# Generated by FakeRAM 2.0 (routing-friendly)
VERSION 5.7 ;
BUSBITCHARS "[]" ;
PROPERTYDEFINITIONS
  MACRO width INTEGER ;
  MACRO depth INTEGER ;
  MACRO banks INTEGER ;
END PROPERTYDEFINITIONS
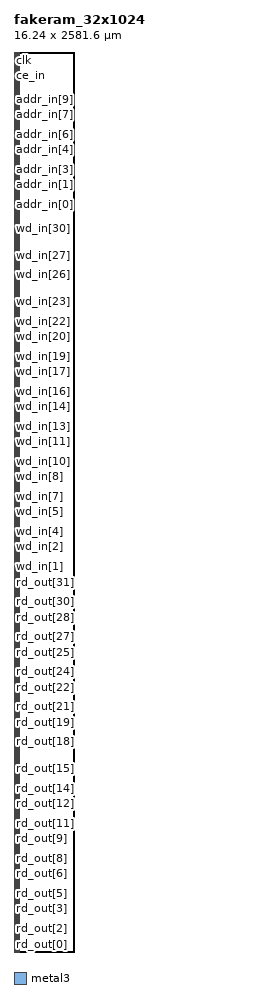
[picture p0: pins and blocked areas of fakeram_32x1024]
MACRO fakeram_32x1024
  PROPERTY width 32 ;
  PROPERTY depth 1024 ;
  PROPERTY banks 1 ;
  FOREIGN fakeram_32x1024 0 0 ;
  SYMMETRY X Y R90 ;
  SIZE 16.240 BY 2581.600 ;
  CLASS BLOCK ;
  PIN rd_out[0]
    DIRECTION OUTPUT ;
    USE SIGNAL ;
    PORT
      LAYER metal3 ;
      RECT 1.000 0.140 3.000 0.210 ;
    END
    PORT
      LAYER metal3 ;
      RECT 1.000 0.105 4.000 0.245 ;
    END
  END rd_out[0]
  PIN rd_out[1]
    DIRECTION OUTPUT ;
    USE SIGNAL ;
    PORT
      LAYER metal3 ;
      RECT 1.000 33.600 3.000 33.670 ;
    END
    PORT
      LAYER metal3 ;
      RECT 1.000 33.565 4.000 33.705 ;
    END
  END rd_out[1]
  PIN rd_out[2]
    DIRECTION OUTPUT ;
    USE SIGNAL ;
    PORT
      LAYER metal3 ;
      RECT 1.000 67.060 3.000 67.130 ;
    END
    PORT
      LAYER metal3 ;
      RECT 1.000 67.025 4.000 67.165 ;
    END
  END rd_out[2]
  PIN rd_out[3]
    DIRECTION OUTPUT ;
    USE SIGNAL ;
    PORT
      LAYER metal3 ;
      RECT 1.000 100.520 3.000 100.590 ;
    END
    PORT
      LAYER metal3 ;
      RECT 1.000 100.485 4.000 100.625 ;
    END
  END rd_out[3]
  PIN rd_out[4]
    DIRECTION OUTPUT ;
    USE SIGNAL ;
    PORT
      LAYER metal3 ;
      RECT 1.000 133.980 3.000 134.050 ;
    END
    PORT
      LAYER metal3 ;
      RECT 1.000 133.945 4.000 134.085 ;
    END
  END rd_out[4]
  PIN rd_out[5]
    DIRECTION OUTPUT ;
    USE SIGNAL ;
    PORT
      LAYER metal3 ;
      RECT 1.000 167.440 3.000 167.510 ;
    END
    PORT
      LAYER metal3 ;
      RECT 1.000 167.405 4.000 167.545 ;
    END
  END rd_out[5]
  PIN rd_out[6]
    DIRECTION OUTPUT ;
    USE SIGNAL ;
    PORT
      LAYER metal3 ;
      RECT 1.000 200.900 3.000 200.970 ;
    END
    PORT
      LAYER metal3 ;
      RECT 1.000 200.865 4.000 201.005 ;
    END
  END rd_out[6]
  PIN rd_out[7]
    DIRECTION OUTPUT ;
    USE SIGNAL ;
    PORT
      LAYER metal3 ;
      RECT 1.000 234.360 3.000 234.430 ;
    END
    PORT
      LAYER metal3 ;
      RECT 1.000 234.325 4.000 234.465 ;
    END
  END rd_out[7]
  PIN rd_out[8]
    DIRECTION OUTPUT ;
    USE SIGNAL ;
    PORT
      LAYER metal3 ;
      RECT 1.000 267.820 3.000 267.890 ;
    END
    PORT
      LAYER metal3 ;
      RECT 1.000 267.785 4.000 267.925 ;
    END
  END rd_out[8]
  PIN rd_out[9]
    DIRECTION OUTPUT ;
    USE SIGNAL ;
    PORT
      LAYER metal3 ;
      RECT 1.000 301.280 3.000 301.350 ;
    END
    PORT
      LAYER metal3 ;
      RECT 1.000 301.245 4.000 301.385 ;
    END
  END rd_out[9]
  PIN rd_out[10]
    DIRECTION OUTPUT ;
    USE SIGNAL ;
    PORT
      LAYER metal3 ;
      RECT 1.000 334.740 3.000 334.810 ;
    END
    PORT
      LAYER metal3 ;
      RECT 1.000 334.705 4.000 334.845 ;
    END
  END rd_out[10]
  PIN rd_out[11]
    DIRECTION OUTPUT ;
    USE SIGNAL ;
    PORT
      LAYER metal3 ;
      RECT 1.000 368.200 3.000 368.270 ;
    END
    PORT
      LAYER metal3 ;
      RECT 1.000 368.165 4.000 368.305 ;
    END
  END rd_out[11]
  PIN rd_out[12]
    DIRECTION OUTPUT ;
    USE SIGNAL ;
    PORT
      LAYER metal3 ;
      RECT 1.000 401.660 3.000 401.730 ;
    END
    PORT
      LAYER metal3 ;
      RECT 1.000 401.625 4.000 401.765 ;
    END
  END rd_out[12]
  PIN rd_out[13]
    DIRECTION OUTPUT ;
    USE SIGNAL ;
    PORT
      LAYER metal3 ;
      RECT 1.000 435.120 3.000 435.190 ;
    END
    PORT
      LAYER metal3 ;
      RECT 1.000 435.085 4.000 435.225 ;
    END
  END rd_out[13]
  PIN rd_out[14]
    DIRECTION OUTPUT ;
    USE SIGNAL ;
    PORT
      LAYER metal3 ;
      RECT 1.000 468.580 3.000 468.650 ;
    END
    PORT
      LAYER metal3 ;
      RECT 1.000 468.545 4.000 468.685 ;
    END
  END rd_out[14]
  PIN rd_out[15]
    DIRECTION OUTPUT ;
    USE SIGNAL ;
    PORT
      LAYER metal3 ;
      RECT 1.000 502.040 3.000 502.110 ;
    END
    PORT
      LAYER metal3 ;
      RECT 1.000 502.005 4.000 502.145 ;
    END
  END rd_out[15]
  PIN rd_out[16]
    DIRECTION OUTPUT ;
    USE SIGNAL ;
    PORT
      LAYER metal3 ;
      RECT 1.000 535.500 3.000 535.570 ;
    END
    PORT
      LAYER metal3 ;
      RECT 1.000 535.465 4.000 535.605 ;
    END
  END rd_out[16]
  PIN rd_out[17]
    DIRECTION OUTPUT ;
    USE SIGNAL ;
    PORT
      LAYER metal3 ;
      RECT 1.000 568.960 3.000 569.030 ;
    END
    PORT
      LAYER metal3 ;
      RECT 1.000 568.925 4.000 569.065 ;
    END
  END rd_out[17]
  PIN rd_out[18]
    DIRECTION OUTPUT ;
    USE SIGNAL ;
    PORT
      LAYER metal3 ;
      RECT 1.000 602.420 3.000 602.490 ;
    END
    PORT
      LAYER metal3 ;
      RECT 1.000 602.385 4.000 602.525 ;
    END
  END rd_out[18]
  PIN rd_out[19]
    DIRECTION OUTPUT ;
    USE SIGNAL ;
    PORT
      LAYER metal3 ;
      RECT 1.000 635.880 3.000 635.950 ;
    END
    PORT
      LAYER metal3 ;
      RECT 1.000 635.845 4.000 635.985 ;
    END
  END rd_out[19]
  PIN rd_out[20]
    DIRECTION OUTPUT ;
    USE SIGNAL ;
    PORT
      LAYER metal3 ;
      RECT 1.000 669.340 3.000 669.410 ;
    END
    PORT
      LAYER metal3 ;
      RECT 1.000 669.305 4.000 669.445 ;
    END
  END rd_out[20]
  PIN rd_out[21]
    DIRECTION OUTPUT ;
    USE SIGNAL ;
    PORT
      LAYER metal3 ;
      RECT 1.000 702.800 3.000 702.870 ;
    END
    PORT
      LAYER metal3 ;
      RECT 1.000 702.765 4.000 702.905 ;
    END
  END rd_out[21]
  PIN rd_out[22]
    DIRECTION OUTPUT ;
    USE SIGNAL ;
    PORT
      LAYER metal3 ;
      RECT 1.000 736.260 3.000 736.330 ;
    END
    PORT
      LAYER metal3 ;
      RECT 1.000 736.225 4.000 736.365 ;
    END
  END rd_out[22]
  PIN rd_out[23]
    DIRECTION OUTPUT ;
    USE SIGNAL ;
    PORT
      LAYER metal3 ;
      RECT 1.000 769.720 3.000 769.790 ;
    END
    PORT
      LAYER metal3 ;
      RECT 1.000 769.685 4.000 769.825 ;
    END
  END rd_out[23]
  PIN rd_out[24]
    DIRECTION OUTPUT ;
    USE SIGNAL ;
    PORT
      LAYER metal3 ;
      RECT 1.000 803.180 3.000 803.250 ;
    END
    PORT
      LAYER metal3 ;
      RECT 1.000 803.145 4.000 803.285 ;
    END
  END rd_out[24]
  PIN rd_out[25]
    DIRECTION OUTPUT ;
    USE SIGNAL ;
    PORT
      LAYER metal3 ;
      RECT 1.000 836.640 3.000 836.710 ;
    END
    PORT
      LAYER metal3 ;
      RECT 1.000 836.605 4.000 836.745 ;
    END
  END rd_out[25]
  PIN rd_out[26]
    DIRECTION OUTPUT ;
    USE SIGNAL ;
    PORT
      LAYER metal3 ;
      RECT 1.000 870.100 3.000 870.170 ;
    END
    PORT
      LAYER metal3 ;
      RECT 1.000 870.065 4.000 870.205 ;
    END
  END rd_out[26]
  PIN rd_out[27]
    DIRECTION OUTPUT ;
    USE SIGNAL ;
    PORT
      LAYER metal3 ;
      RECT 1.000 903.560 3.000 903.630 ;
    END
    PORT
      LAYER metal3 ;
      RECT 1.000 903.525 4.000 903.665 ;
    END
  END rd_out[27]
  PIN rd_out[28]
    DIRECTION OUTPUT ;
    USE SIGNAL ;
    PORT
      LAYER metal3 ;
      RECT 1.000 937.020 3.000 937.090 ;
    END
    PORT
      LAYER metal3 ;
      RECT 1.000 936.985 4.000 937.125 ;
    END
  END rd_out[28]
  PIN rd_out[29]
    DIRECTION OUTPUT ;
    USE SIGNAL ;
    PORT
      LAYER metal3 ;
      RECT 1.000 970.480 3.000 970.550 ;
    END
    PORT
      LAYER metal3 ;
      RECT 1.000 970.445 4.000 970.585 ;
    END
  END rd_out[29]
  PIN rd_out[30]
    DIRECTION OUTPUT ;
    USE SIGNAL ;
    PORT
      LAYER metal3 ;
      RECT 1.000 1003.940 3.000 1004.010 ;
    END
    PORT
      LAYER metal3 ;
      RECT 1.000 1003.905 4.000 1004.045 ;
    END
  END rd_out[30]
  PIN rd_out[31]
    DIRECTION OUTPUT ;
    USE SIGNAL ;
    PORT
      LAYER metal3 ;
      RECT 1.000 1037.400 3.000 1037.470 ;
    END
    PORT
      LAYER metal3 ;
      RECT 1.000 1037.365 4.000 1037.505 ;
    END
  END rd_out[31]
  PIN wd_in[0]
    DIRECTION INPUT ;
    USE SIGNAL ;
    PORT
      LAYER metal3 ;
      RECT 1.000 1072.400 3.000 1072.470 ;
    END
    PORT
      LAYER metal3 ;
      RECT 1.000 1072.365 4.000 1072.505 ;
    END
  END wd_in[0]
  PIN wd_in[1]
    DIRECTION INPUT ;
    USE SIGNAL ;
    PORT
      LAYER metal3 ;
      RECT 1.000 1105.860 3.000 1105.930 ;
    END
    PORT
      LAYER metal3 ;
      RECT 1.000 1105.825 4.000 1105.965 ;
    END
  END wd_in[1]
  PIN wd_in[2]
    DIRECTION INPUT ;
    USE SIGNAL ;
    PORT
      LAYER metal3 ;
      RECT 1.000 1139.320 3.000 1139.390 ;
    END
    PORT
      LAYER metal3 ;
      RECT 1.000 1139.285 4.000 1139.425 ;
    END
  END wd_in[2]
  PIN wd_in[3]
    DIRECTION INPUT ;
    USE SIGNAL ;
    PORT
      LAYER metal3 ;
      RECT 1.000 1172.780 3.000 1172.850 ;
    END
    PORT
      LAYER metal3 ;
      RECT 1.000 1172.745 4.000 1172.885 ;
    END
  END wd_in[3]
  PIN wd_in[4]
    DIRECTION INPUT ;
    USE SIGNAL ;
    PORT
      LAYER metal3 ;
      RECT 1.000 1206.240 3.000 1206.310 ;
    END
    PORT
      LAYER metal3 ;
      RECT 1.000 1206.205 4.000 1206.345 ;
    END
  END wd_in[4]
  PIN wd_in[5]
    DIRECTION INPUT ;
    USE SIGNAL ;
    PORT
      LAYER metal3 ;
      RECT 1.000 1239.700 3.000 1239.770 ;
    END
    PORT
      LAYER metal3 ;
      RECT 1.000 1239.665 4.000 1239.805 ;
    END
  END wd_in[5]
  PIN wd_in[6]
    DIRECTION INPUT ;
    USE SIGNAL ;
    PORT
      LAYER metal3 ;
      RECT 1.000 1273.160 3.000 1273.230 ;
    END
    PORT
      LAYER metal3 ;
      RECT 1.000 1273.125 4.000 1273.265 ;
    END
  END wd_in[6]
  PIN wd_in[7]
    DIRECTION INPUT ;
    USE SIGNAL ;
    PORT
      LAYER metal3 ;
      RECT 1.000 1306.620 3.000 1306.690 ;
    END
    PORT
      LAYER metal3 ;
      RECT 1.000 1306.585 4.000 1306.725 ;
    END
  END wd_in[7]
  PIN wd_in[8]
    DIRECTION INPUT ;
    USE SIGNAL ;
    PORT
      LAYER metal3 ;
      RECT 1.000 1340.080 3.000 1340.150 ;
    END
    PORT
      LAYER metal3 ;
      RECT 1.000 1340.045 4.000 1340.185 ;
    END
  END wd_in[8]
  PIN wd_in[9]
    DIRECTION INPUT ;
    USE SIGNAL ;
    PORT
      LAYER metal3 ;
      RECT 1.000 1373.540 3.000 1373.610 ;
    END
    PORT
      LAYER metal3 ;
      RECT 1.000 1373.505 4.000 1373.645 ;
    END
  END wd_in[9]
  PIN wd_in[10]
    DIRECTION INPUT ;
    USE SIGNAL ;
    PORT
      LAYER metal3 ;
      RECT 1.000 1407.000 3.000 1407.070 ;
    END
    PORT
      LAYER metal3 ;
      RECT 1.000 1406.965 4.000 1407.105 ;
    END
  END wd_in[10]
  PIN wd_in[11]
    DIRECTION INPUT ;
    USE SIGNAL ;
    PORT
      LAYER metal3 ;
      RECT 1.000 1440.460 3.000 1440.530 ;
    END
    PORT
      LAYER metal3 ;
      RECT 1.000 1440.425 4.000 1440.565 ;
    END
  END wd_in[11]
  PIN wd_in[12]
    DIRECTION INPUT ;
    USE SIGNAL ;
    PORT
      LAYER metal3 ;
      RECT 1.000 1473.920 3.000 1473.990 ;
    END
    PORT
      LAYER metal3 ;
      RECT 1.000 1473.885 4.000 1474.025 ;
    END
  END wd_in[12]
  PIN wd_in[13]
    DIRECTION INPUT ;
    USE SIGNAL ;
    PORT
      LAYER metal3 ;
      RECT 1.000 1507.380 3.000 1507.450 ;
    END
    PORT
      LAYER metal3 ;
      RECT 1.000 1507.345 4.000 1507.485 ;
    END
  END wd_in[13]
  PIN wd_in[14]
    DIRECTION INPUT ;
    USE SIGNAL ;
    PORT
      LAYER metal3 ;
      RECT 1.000 1540.840 3.000 1540.910 ;
    END
    PORT
      LAYER metal3 ;
      RECT 1.000 1540.805 4.000 1540.945 ;
    END
  END wd_in[14]
  PIN wd_in[15]
    DIRECTION INPUT ;
    USE SIGNAL ;
    PORT
      LAYER metal3 ;
      RECT 1.000 1574.300 3.000 1574.370 ;
    END
    PORT
      LAYER metal3 ;
      RECT 1.000 1574.265 4.000 1574.405 ;
    END
  END wd_in[15]
  PIN wd_in[16]
    DIRECTION INPUT ;
    USE SIGNAL ;
    PORT
      LAYER metal3 ;
      RECT 1.000 1607.760 3.000 1607.830 ;
    END
    PORT
      LAYER metal3 ;
      RECT 1.000 1607.725 4.000 1607.865 ;
    END
  END wd_in[16]
  PIN wd_in[17]
    DIRECTION INPUT ;
    USE SIGNAL ;
    PORT
      LAYER metal3 ;
      RECT 1.000 1641.220 3.000 1641.290 ;
    END
    PORT
      LAYER metal3 ;
      RECT 1.000 1641.185 4.000 1641.325 ;
    END
  END wd_in[17]
  PIN wd_in[18]
    DIRECTION INPUT ;
    USE SIGNAL ;
    PORT
      LAYER metal3 ;
      RECT 1.000 1674.680 3.000 1674.750 ;
    END
    PORT
      LAYER metal3 ;
      RECT 1.000 1674.645 4.000 1674.785 ;
    END
  END wd_in[18]
  PIN wd_in[19]
    DIRECTION INPUT ;
    USE SIGNAL ;
    PORT
      LAYER metal3 ;
      RECT 1.000 1708.140 3.000 1708.210 ;
    END
    PORT
      LAYER metal3 ;
      RECT 1.000 1708.105 4.000 1708.245 ;
    END
  END wd_in[19]
  PIN wd_in[20]
    DIRECTION INPUT ;
    USE SIGNAL ;
    PORT
      LAYER metal3 ;
      RECT 1.000 1741.600 3.000 1741.670 ;
    END
    PORT
      LAYER metal3 ;
      RECT 1.000 1741.565 4.000 1741.705 ;
    END
  END wd_in[20]
  PIN wd_in[21]
    DIRECTION INPUT ;
    USE SIGNAL ;
    PORT
      LAYER metal3 ;
      RECT 1.000 1775.060 3.000 1775.130 ;
    END
    PORT
      LAYER metal3 ;
      RECT 1.000 1775.025 4.000 1775.165 ;
    END
  END wd_in[21]
  PIN wd_in[22]
    DIRECTION INPUT ;
    USE SIGNAL ;
    PORT
      LAYER metal3 ;
      RECT 1.000 1808.520 3.000 1808.590 ;
    END
    PORT
      LAYER metal3 ;
      RECT 1.000 1808.485 4.000 1808.625 ;
    END
  END wd_in[22]
  PIN wd_in[23]
    DIRECTION INPUT ;
    USE SIGNAL ;
    PORT
      LAYER metal3 ;
      RECT 1.000 1841.980 3.000 1842.050 ;
    END
    PORT
      LAYER metal3 ;
      RECT 1.000 1841.945 4.000 1842.085 ;
    END
  END wd_in[23]
  PIN wd_in[24]
    DIRECTION INPUT ;
    USE SIGNAL ;
    PORT
      LAYER metal3 ;
      RECT 1.000 1875.440 3.000 1875.510 ;
    END
    PORT
      LAYER metal3 ;
      RECT 1.000 1875.405 4.000 1875.545 ;
    END
  END wd_in[24]
  PIN wd_in[25]
    DIRECTION INPUT ;
    USE SIGNAL ;
    PORT
      LAYER metal3 ;
      RECT 1.000 1908.900 3.000 1908.970 ;
    END
    PORT
      LAYER metal3 ;
      RECT 1.000 1908.865 4.000 1909.005 ;
    END
  END wd_in[25]
  PIN wd_in[26]
    DIRECTION INPUT ;
    USE SIGNAL ;
    PORT
      LAYER metal3 ;
      RECT 1.000 1942.360 3.000 1942.430 ;
    END
    PORT
      LAYER metal3 ;
      RECT 1.000 1942.325 4.000 1942.465 ;
    END
  END wd_in[26]
  PIN wd_in[27]
    DIRECTION INPUT ;
    USE SIGNAL ;
    PORT
      LAYER metal3 ;
      RECT 1.000 1975.820 3.000 1975.890 ;
    END
    PORT
      LAYER metal3 ;
      RECT 1.000 1975.785 4.000 1975.925 ;
    END
  END wd_in[27]
  PIN wd_in[28]
    DIRECTION INPUT ;
    USE SIGNAL ;
    PORT
      LAYER metal3 ;
      RECT 1.000 2009.280 3.000 2009.350 ;
    END
    PORT
      LAYER metal3 ;
      RECT 1.000 2009.245 4.000 2009.385 ;
    END
  END wd_in[28]
  PIN wd_in[29]
    DIRECTION INPUT ;
    USE SIGNAL ;
    PORT
      LAYER metal3 ;
      RECT 1.000 2042.740 3.000 2042.810 ;
    END
    PORT
      LAYER metal3 ;
      RECT 1.000 2042.705 4.000 2042.845 ;
    END
  END wd_in[29]
  PIN wd_in[30]
    DIRECTION INPUT ;
    USE SIGNAL ;
    PORT
      LAYER metal3 ;
      RECT 1.000 2076.200 3.000 2076.270 ;
    END
    PORT
      LAYER metal3 ;
      RECT 1.000 2076.165 4.000 2076.305 ;
    END
  END wd_in[30]
  PIN wd_in[31]
    DIRECTION INPUT ;
    USE SIGNAL ;
    PORT
      LAYER metal3 ;
      RECT 1.000 2109.660 3.000 2109.730 ;
    END
    PORT
      LAYER metal3 ;
      RECT 1.000 2109.625 4.000 2109.765 ;
    END
  END wd_in[31]
  PIN addr_in[0]
    DIRECTION INPUT ;
    USE SIGNAL ;
    PORT
      LAYER metal3 ;
      RECT 1.000 2144.660 3.000 2144.730 ;
    END
    PORT
      LAYER metal3 ;
      RECT 1.000 2144.625 4.000 2144.765 ;
    END
  END addr_in[0]
  PIN addr_in[1]
    DIRECTION INPUT ;
    USE SIGNAL ;
    PORT
      LAYER metal3 ;
      RECT 1.000 2178.120 3.000 2178.190 ;
    END
    PORT
      LAYER metal3 ;
      RECT 1.000 2178.085 4.000 2178.225 ;
    END
  END addr_in[1]
  PIN addr_in[2]
    DIRECTION INPUT ;
    USE SIGNAL ;
    PORT
      LAYER metal3 ;
      RECT 1.000 2211.580 3.000 2211.650 ;
    END
    PORT
      LAYER metal3 ;
      RECT 1.000 2211.545 4.000 2211.685 ;
    END
  END addr_in[2]
  PIN addr_in[3]
    DIRECTION INPUT ;
    USE SIGNAL ;
    PORT
      LAYER metal3 ;
      RECT 1.000 2245.040 3.000 2245.110 ;
    END
    PORT
      LAYER metal3 ;
      RECT 1.000 2245.005 4.000 2245.145 ;
    END
  END addr_in[3]
  PIN addr_in[4]
    DIRECTION INPUT ;
    USE SIGNAL ;
    PORT
      LAYER metal3 ;
      RECT 1.000 2278.500 3.000 2278.570 ;
    END
    PORT
      LAYER metal3 ;
      RECT 1.000 2278.465 4.000 2278.605 ;
    END
  END addr_in[4]
  PIN addr_in[5]
    DIRECTION INPUT ;
    USE SIGNAL ;
    PORT
      LAYER metal3 ;
      RECT 1.000 2311.960 3.000 2312.030 ;
    END
    PORT
      LAYER metal3 ;
      RECT 1.000 2311.925 4.000 2312.065 ;
    END
  END addr_in[5]
  PIN addr_in[6]
    DIRECTION INPUT ;
    USE SIGNAL ;
    PORT
      LAYER metal3 ;
      RECT 1.000 2345.420 3.000 2345.490 ;
    END
    PORT
      LAYER metal3 ;
      RECT 1.000 2345.385 4.000 2345.525 ;
    END
  END addr_in[6]
  PIN addr_in[7]
    DIRECTION INPUT ;
    USE SIGNAL ;
    PORT
      LAYER metal3 ;
      RECT 1.000 2378.880 3.000 2378.950 ;
    END
    PORT
      LAYER metal3 ;
      RECT 1.000 2378.845 4.000 2378.985 ;
    END
  END addr_in[7]
  PIN addr_in[8]
    DIRECTION INPUT ;
    USE SIGNAL ;
    PORT
      LAYER metal3 ;
      RECT 1.000 2412.340 3.000 2412.410 ;
    END
    PORT
      LAYER metal3 ;
      RECT 1.000 2412.305 4.000 2412.445 ;
    END
  END addr_in[8]
  PIN addr_in[9]
    DIRECTION INPUT ;
    USE SIGNAL ;
    PORT
      LAYER metal3 ;
      RECT 1.000 2445.800 3.000 2445.870 ;
    END
    PORT
      LAYER metal3 ;
      RECT 1.000 2445.765 4.000 2445.905 ;
    END
  END addr_in[9]
  PIN we_in
    DIRECTION INPUT ;
    USE SIGNAL ;
    PORT
      LAYER metal3 ;
      RECT 1.000 2480.800 3.000 2480.870 ;
    END
    PORT
      LAYER metal3 ;
      RECT 1.000 2480.765 4.000 2480.905 ;
    END
  END we_in
  PIN ce_in
    DIRECTION INPUT ;
    USE SIGNAL ;
    PORT
      LAYER metal3 ;
      RECT 1.000 2514.260 3.000 2514.330 ;
    END
    PORT
      LAYER metal3 ;
      RECT 1.000 2514.225 4.000 2514.365 ;
    END
  END ce_in
  PIN clk
    DIRECTION INPUT ;
    USE SIGNAL ;
    PORT
      LAYER metal3 ;
      RECT 1.000 2547.720 3.000 2547.790 ;
    END
    PORT
      LAYER metal3 ;
      RECT 1.000 2547.685 4.000 2547.825 ;
    END
  END clk
  PIN VSS
    DIRECTION INOUT ;
    USE GROUND ;
    PORT
      LAYER metal3 ;
      RECT 0.140 0.000 16.100 0.280 ;
      RECT 0.140 2.240 16.100 2.520 ;
      RECT 0.140 4.480 16.100 4.760 ;
      RECT 0.140 6.720 16.100 7.000 ;
      RECT 0.140 8.960 16.100 9.240 ;
      RECT 0.140 11.200 16.100 11.480 ;
      RECT 0.140 13.440 16.100 13.720 ;
      RECT 0.140 15.680 16.100 15.960 ;
      RECT 0.140 17.920 16.100 18.200 ;
      RECT 0.140 20.160 16.100 20.440 ;
      RECT 0.140 22.400 16.100 22.680 ;
      RECT 0.140 24.640 16.100 24.920 ;
      RECT 0.140 26.880 16.100 27.160 ;
      RECT 0.140 29.120 16.100 29.400 ;
      RECT 0.140 31.360 16.100 31.640 ;
      RECT 0.140 33.600 16.100 33.880 ;
      RECT 0.140 35.840 16.100 36.120 ;
      RECT 0.140 38.080 16.100 38.360 ;
      RECT 0.140 40.320 16.100 40.600 ;
      RECT 0.140 42.560 16.100 42.840 ;
      RECT 0.140 44.800 16.100 45.080 ;
      RECT 0.140 47.040 16.100 47.320 ;
      RECT 0.140 49.280 16.100 49.560 ;
      RECT 0.140 51.520 16.100 51.800 ;
      RECT 0.140 53.760 16.100 54.040 ;
      RECT 0.140 56.000 16.100 56.280 ;
      RECT 0.140 58.240 16.100 58.520 ;
      RECT 0.140 60.480 16.100 60.760 ;
      RECT 0.140 62.720 16.100 63.000 ;
      RECT 0.140 64.960 16.100 65.240 ;
      RECT 0.140 67.200 16.100 67.480 ;
      RECT 0.140 69.440 16.100 69.720 ;
      RECT 0.140 71.680 16.100 71.960 ;
      RECT 0.140 73.920 16.100 74.200 ;
      RECT 0.140 76.160 16.100 76.440 ;
      RECT 0.140 78.400 16.100 78.680 ;
      RECT 0.140 80.640 16.100 80.920 ;
      RECT 0.140 82.880 16.100 83.160 ;
      RECT 0.140 85.120 16.100 85.400 ;
      RECT 0.140 87.360 16.100 87.640 ;
      RECT 0.140 89.600 16.100 89.880 ;
      RECT 0.140 91.840 16.100 92.120 ;
      RECT 0.140 94.080 16.100 94.360 ;
      RECT 0.140 96.320 16.100 96.600 ;
      RECT 0.140 98.560 16.100 98.840 ;
      RECT 0.140 100.800 16.100 101.080 ;
      RECT 0.140 103.040 16.100 103.320 ;
      RECT 0.140 105.280 16.100 105.560 ;
      RECT 0.140 107.520 16.100 107.800 ;
      RECT 0.140 109.760 16.100 110.040 ;
      RECT 0.140 112.000 16.100 112.280 ;
      RECT 0.140 114.240 16.100 114.520 ;
      RECT 0.140 116.480 16.100 116.760 ;
      RECT 0.140 118.720 16.100 119.000 ;
      RECT 0.140 120.960 16.100 121.240 ;
      RECT 0.140 123.200 16.100 123.480 ;
      RECT 0.140 125.440 16.100 125.720 ;
      RECT 0.140 127.680 16.100 127.960 ;
      RECT 0.140 129.920 16.100 130.200 ;
      RECT 0.140 132.160 16.100 132.440 ;
      RECT 0.140 134.400 16.100 134.680 ;
      RECT 0.140 136.640 16.100 136.920 ;
      RECT 0.140 138.880 16.100 139.160 ;
      RECT 0.140 141.120 16.100 141.400 ;
      RECT 0.140 143.360 16.100 143.640 ;
      RECT 0.140 145.600 16.100 145.880 ;
      RECT 0.140 147.840 16.100 148.120 ;
      RECT 0.140 150.080 16.100 150.360 ;
      RECT 0.140 152.320 16.100 152.600 ;
      RECT 0.140 154.560 16.100 154.840 ;
      RECT 0.140 156.800 16.100 157.080 ;
      RECT 0.140 159.040 16.100 159.320 ;
      RECT 0.140 161.280 16.100 161.560 ;
      RECT 0.140 163.520 16.100 163.800 ;
      RECT 0.140 165.760 16.100 166.040 ;
      RECT 0.140 168.000 16.100 168.280 ;
      RECT 0.140 170.240 16.100 170.520 ;
      RECT 0.140 172.480 16.100 172.760 ;
      RECT 0.140 174.720 16.100 175.000 ;
      RECT 0.140 176.960 16.100 177.240 ;
      RECT 0.140 179.200 16.100 179.480 ;
      RECT 0.140 181.440 16.100 181.720 ;
      RECT 0.140 183.680 16.100 183.960 ;
      RECT 0.140 185.920 16.100 186.200 ;
      RECT 0.140 188.160 16.100 188.440 ;
      RECT 0.140 190.400 16.100 190.680 ;
      RECT 0.140 192.640 16.100 192.920 ;
      RECT 0.140 194.880 16.100 195.160 ;
      RECT 0.140 197.120 16.100 197.400 ;
      RECT 0.140 199.360 16.100 199.640 ;
      RECT 0.140 201.600 16.100 201.880 ;
      RECT 0.140 203.840 16.100 204.120 ;
      RECT 0.140 206.080 16.100 206.360 ;
      RECT 0.140 208.320 16.100 208.600 ;
      RECT 0.140 210.560 16.100 210.840 ;
      RECT 0.140 212.800 16.100 213.080 ;
      RECT 0.140 215.040 16.100 215.320 ;
      RECT 0.140 217.280 16.100 217.560 ;
      RECT 0.140 219.520 16.100 219.800 ;
      RECT 0.140 221.760 16.100 222.040 ;
      RECT 0.140 224.000 16.100 224.280 ;
      RECT 0.140 226.240 16.100 226.520 ;
      RECT 0.140 228.480 16.100 228.760 ;
      RECT 0.140 230.720 16.100 231.000 ;
      RECT 0.140 232.960 16.100 233.240 ;
      RECT 0.140 235.200 16.100 235.480 ;
      RECT 0.140 237.440 16.100 237.720 ;
      RECT 0.140 239.680 16.100 239.960 ;
      RECT 0.140 241.920 16.100 242.200 ;
      RECT 0.140 244.160 16.100 244.440 ;
      RECT 0.140 246.400 16.100 246.680 ;
      RECT 0.140 248.640 16.100 248.920 ;
      RECT 0.140 250.880 16.100 251.160 ;
      RECT 0.140 253.120 16.100 253.400 ;
      RECT 0.140 255.360 16.100 255.640 ;
      RECT 0.140 257.600 16.100 257.880 ;
      RECT 0.140 259.840 16.100 260.120 ;
      RECT 0.140 262.080 16.100 262.360 ;
      RECT 0.140 264.320 16.100 264.600 ;
      RECT 0.140 266.560 16.100 266.840 ;
      RECT 0.140 268.800 16.100 269.080 ;
      RECT 0.140 271.040 16.100 271.320 ;
      RECT 0.140 273.280 16.100 273.560 ;
      RECT 0.140 275.520 16.100 275.800 ;
      RECT 0.140 277.760 16.100 278.040 ;
      RECT 0.140 280.000 16.100 280.280 ;
      RECT 0.140 282.240 16.100 282.520 ;
      RECT 0.140 284.480 16.100 284.760 ;
      RECT 0.140 286.720 16.100 287.000 ;
      RECT 0.140 288.960 16.100 289.240 ;
      RECT 0.140 291.200 16.100 291.480 ;
      RECT 0.140 293.440 16.100 293.720 ;
      RECT 0.140 295.680 16.100 295.960 ;
      RECT 0.140 297.920 16.100 298.200 ;
      RECT 0.140 300.160 16.100 300.440 ;
      RECT 0.140 302.400 16.100 302.680 ;
      RECT 0.140 304.640 16.100 304.920 ;
      RECT 0.140 306.880 16.100 307.160 ;
      RECT 0.140 309.120 16.100 309.400 ;
      RECT 0.140 311.360 16.100 311.640 ;
      RECT 0.140 313.600 16.100 313.880 ;
      RECT 0.140 315.840 16.100 316.120 ;
      RECT 0.140 318.080 16.100 318.360 ;
      RECT 0.140 320.320 16.100 320.600 ;
      RECT 0.140 322.560 16.100 322.840 ;
      RECT 0.140 324.800 16.100 325.080 ;
      RECT 0.140 327.040 16.100 327.320 ;
      RECT 0.140 329.280 16.100 329.560 ;
      RECT 0.140 331.520 16.100 331.800 ;
      RECT 0.140 333.760 16.100 334.040 ;
      RECT 0.140 336.000 16.100 336.280 ;
      RECT 0.140 338.240 16.100 338.520 ;
      RECT 0.140 340.480 16.100 340.760 ;
      RECT 0.140 342.720 16.100 343.000 ;
      RECT 0.140 344.960 16.100 345.240 ;
      RECT 0.140 347.200 16.100 347.480 ;
      RECT 0.140 349.440 16.100 349.720 ;
      RECT 0.140 351.680 16.100 351.960 ;
      RECT 0.140 353.920 16.100 354.200 ;
      RECT 0.140 356.160 16.100 356.440 ;
      RECT 0.140 358.400 16.100 358.680 ;
      RECT 0.140 360.640 16.100 360.920 ;
      RECT 0.140 362.880 16.100 363.160 ;
      RECT 0.140 365.120 16.100 365.400 ;
      RECT 0.140 367.360 16.100 367.640 ;
      RECT 0.140 369.600 16.100 369.880 ;
      RECT 0.140 371.840 16.100 372.120 ;
      RECT 0.140 374.080 16.100 374.360 ;
      RECT 0.140 376.320 16.100 376.600 ;
      RECT 0.140 378.560 16.100 378.840 ;
      RECT 0.140 380.800 16.100 381.080 ;
      RECT 0.140 383.040 16.100 383.320 ;
      RECT 0.140 385.280 16.100 385.560 ;
      RECT 0.140 387.520 16.100 387.800 ;
      RECT 0.140 389.760 16.100 390.040 ;
      RECT 0.140 392.000 16.100 392.280 ;
      RECT 0.140 394.240 16.100 394.520 ;
      RECT 0.140 396.480 16.100 396.760 ;
      RECT 0.140 398.720 16.100 399.000 ;
      RECT 0.140 400.960 16.100 401.240 ;
      RECT 0.140 403.200 16.100 403.480 ;
      RECT 0.140 405.440 16.100 405.720 ;
      RECT 0.140 407.680 16.100 407.960 ;
      RECT 0.140 409.920 16.100 410.200 ;
      RECT 0.140 412.160 16.100 412.440 ;
      RECT 0.140 414.400 16.100 414.680 ;
      RECT 0.140 416.640 16.100 416.920 ;
      RECT 0.140 418.880 16.100 419.160 ;
      RECT 0.140 421.120 16.100 421.400 ;
      RECT 0.140 423.360 16.100 423.640 ;
      RECT 0.140 425.600 16.100 425.880 ;
      RECT 0.140 427.840 16.100 428.120 ;
      RECT 0.140 430.080 16.100 430.360 ;
      RECT 0.140 432.320 16.100 432.600 ;
      RECT 0.140 434.560 16.100 434.840 ;
      RECT 0.140 436.800 16.100 437.080 ;
      RECT 0.140 439.040 16.100 439.320 ;
      RECT 0.140 441.280 16.100 441.560 ;
      RECT 0.140 443.520 16.100 443.800 ;
      RECT 0.140 445.760 16.100 446.040 ;
      RECT 0.140 448.000 16.100 448.280 ;
      RECT 0.140 450.240 16.100 450.520 ;
      RECT 0.140 452.480 16.100 452.760 ;
      RECT 0.140 454.720 16.100 455.000 ;
      RECT 0.140 456.960 16.100 457.240 ;
      RECT 0.140 459.200 16.100 459.480 ;
      RECT 0.140 461.440 16.100 461.720 ;
      RECT 0.140 463.680 16.100 463.960 ;
      RECT 0.140 465.920 16.100 466.200 ;
      RECT 0.140 468.160 16.100 468.440 ;
      RECT 0.140 470.400 16.100 470.680 ;
      RECT 0.140 472.640 16.100 472.920 ;
      RECT 0.140 474.880 16.100 475.160 ;
      RECT 0.140 477.120 16.100 477.400 ;
      RECT 0.140 479.360 16.100 479.640 ;
      RECT 0.140 481.600 16.100 481.880 ;
      RECT 0.140 483.840 16.100 484.120 ;
      RECT 0.140 486.080 16.100 486.360 ;
      RECT 0.140 488.320 16.100 488.600 ;
      RECT 0.140 490.560 16.100 490.840 ;
      RECT 0.140 492.800 16.100 493.080 ;
      RECT 0.140 495.040 16.100 495.320 ;
      RECT 0.140 497.280 16.100 497.560 ;
      RECT 0.140 499.520 16.100 499.800 ;
      RECT 0.140 501.760 16.100 502.040 ;
      RECT 0.140 504.000 16.100 504.280 ;
      RECT 0.140 506.240 16.100 506.520 ;
      RECT 0.140 508.480 16.100 508.760 ;
      RECT 0.140 510.720 16.100 511.000 ;
      RECT 0.140 512.960 16.100 513.240 ;
      RECT 0.140 515.200 16.100 515.480 ;
      RECT 0.140 517.440 16.100 517.720 ;
      RECT 0.140 519.680 16.100 519.960 ;
      RECT 0.140 521.920 16.100 522.200 ;
      RECT 0.140 524.160 16.100 524.440 ;
      RECT 0.140 526.400 16.100 526.680 ;
      RECT 0.140 528.640 16.100 528.920 ;
      RECT 0.140 530.880 16.100 531.160 ;
      RECT 0.140 533.120 16.100 533.400 ;
      RECT 0.140 535.360 16.100 535.640 ;
      RECT 0.140 537.600 16.100 537.880 ;
      RECT 0.140 539.840 16.100 540.120 ;
      RECT 0.140 542.080 16.100 542.360 ;
      RECT 0.140 544.320 16.100 544.600 ;
      RECT 0.140 546.560 16.100 546.840 ;
      RECT 0.140 548.800 16.100 549.080 ;
      RECT 0.140 551.040 16.100 551.320 ;
      RECT 0.140 553.280 16.100 553.560 ;
      RECT 0.140 555.520 16.100 555.800 ;
      RECT 0.140 557.760 16.100 558.040 ;
      RECT 0.140 560.000 16.100 560.280 ;
      RECT 0.140 562.240 16.100 562.520 ;
      RECT 0.140 564.480 16.100 564.760 ;
      RECT 0.140 566.720 16.100 567.000 ;
      RECT 0.140 568.960 16.100 569.240 ;
      RECT 0.140 571.200 16.100 571.480 ;
      RECT 0.140 573.440 16.100 573.720 ;
      RECT 0.140 575.680 16.100 575.960 ;
      RECT 0.140 577.920 16.100 578.200 ;
      RECT 0.140 580.160 16.100 580.440 ;
      RECT 0.140 582.400 16.100 582.680 ;
      RECT 0.140 584.640 16.100 584.920 ;
      RECT 0.140 586.880 16.100 587.160 ;
      RECT 0.140 589.120 16.100 589.400 ;
      RECT 0.140 591.360 16.100 591.640 ;
      RECT 0.140 593.600 16.100 593.880 ;
      RECT 0.140 595.840 16.100 596.120 ;
      RECT 0.140 598.080 16.100 598.360 ;
      RECT 0.140 600.320 16.100 600.600 ;
      RECT 0.140 602.560 16.100 602.840 ;
      RECT 0.140 604.800 16.100 605.080 ;
      RECT 0.140 607.040 16.100 607.320 ;
      RECT 0.140 609.280 16.100 609.560 ;
      RECT 0.140 611.520 16.100 611.800 ;
      RECT 0.140 613.760 16.100 614.040 ;
      RECT 0.140 616.000 16.100 616.280 ;
      RECT 0.140 618.240 16.100 618.520 ;
      RECT 0.140 620.480 16.100 620.760 ;
      RECT 0.140 622.720 16.100 623.000 ;
      RECT 0.140 624.960 16.100 625.240 ;
      RECT 0.140 627.200 16.100 627.480 ;
      RECT 0.140 629.440 16.100 629.720 ;
      RECT 0.140 631.680 16.100 631.960 ;
      RECT 0.140 633.920 16.100 634.200 ;
      RECT 0.140 636.160 16.100 636.440 ;
      RECT 0.140 638.400 16.100 638.680 ;
      RECT 0.140 640.640 16.100 640.920 ;
      RECT 0.140 642.880 16.100 643.160 ;
      RECT 0.140 645.120 16.100 645.400 ;
      RECT 0.140 647.360 16.100 647.640 ;
      RECT 0.140 649.600 16.100 649.880 ;
      RECT 0.140 651.840 16.100 652.120 ;
      RECT 0.140 654.080 16.100 654.360 ;
      RECT 0.140 656.320 16.100 656.600 ;
      RECT 0.140 658.560 16.100 658.840 ;
      RECT 0.140 660.800 16.100 661.080 ;
      RECT 0.140 663.040 16.100 663.320 ;
      RECT 0.140 665.280 16.100 665.560 ;
      RECT 0.140 667.520 16.100 667.800 ;
      RECT 0.140 669.760 16.100 670.040 ;
      RECT 0.140 672.000 16.100 672.280 ;
      RECT 0.140 674.240 16.100 674.520 ;
      RECT 0.140 676.480 16.100 676.760 ;
      RECT 0.140 678.720 16.100 679.000 ;
      RECT 0.140 680.960 16.100 681.240 ;
      RECT 0.140 683.200 16.100 683.480 ;
      RECT 0.140 685.440 16.100 685.720 ;
      RECT 0.140 687.680 16.100 687.960 ;
      RECT 0.140 689.920 16.100 690.200 ;
      RECT 0.140 692.160 16.100 692.440 ;
      RECT 0.140 694.400 16.100 694.680 ;
      RECT 0.140 696.640 16.100 696.920 ;
      RECT 0.140 698.880 16.100 699.160 ;
      RECT 0.140 701.120 16.100 701.400 ;
      RECT 0.140 703.360 16.100 703.640 ;
      RECT 0.140 705.600 16.100 705.880 ;
      RECT 0.140 707.840 16.100 708.120 ;
      RECT 0.140 710.080 16.100 710.360 ;
      RECT 0.140 712.320 16.100 712.600 ;
      RECT 0.140 714.560 16.100 714.840 ;
      RECT 0.140 716.800 16.100 717.080 ;
      RECT 0.140 719.040 16.100 719.320 ;
      RECT 0.140 721.280 16.100 721.560 ;
      RECT 0.140 723.520 16.100 723.800 ;
      RECT 0.140 725.760 16.100 726.040 ;
      RECT 0.140 728.000 16.100 728.280 ;
      RECT 0.140 730.240 16.100 730.520 ;
      RECT 0.140 732.480 16.100 732.760 ;
      RECT 0.140 734.720 16.100 735.000 ;
      RECT 0.140 736.960 16.100 737.240 ;
      RECT 0.140 739.200 16.100 739.480 ;
      RECT 0.140 741.440 16.100 741.720 ;
      RECT 0.140 743.680 16.100 743.960 ;
      RECT 0.140 745.920 16.100 746.200 ;
      RECT 0.140 748.160 16.100 748.440 ;
      RECT 0.140 750.400 16.100 750.680 ;
      RECT 0.140 752.640 16.100 752.920 ;
      RECT 0.140 754.880 16.100 755.160 ;
      RECT 0.140 757.120 16.100 757.400 ;
      RECT 0.140 759.360 16.100 759.640 ;
      RECT 0.140 761.600 16.100 761.880 ;
      RECT 0.140 763.840 16.100 764.120 ;
      RECT 0.140 766.080 16.100 766.360 ;
      RECT 0.140 768.320 16.100 768.600 ;
      RECT 0.140 770.560 16.100 770.840 ;
      RECT 0.140 772.800 16.100 773.080 ;
      RECT 0.140 775.040 16.100 775.320 ;
      RECT 0.140 777.280 16.100 777.560 ;
      RECT 0.140 779.520 16.100 779.800 ;
      RECT 0.140 781.760 16.100 782.040 ;
      RECT 0.140 784.000 16.100 784.280 ;
      RECT 0.140 786.240 16.100 786.520 ;
      RECT 0.140 788.480 16.100 788.760 ;
      RECT 0.140 790.720 16.100 791.000 ;
      RECT 0.140 792.960 16.100 793.240 ;
      RECT 0.140 795.200 16.100 795.480 ;
      RECT 0.140 797.440 16.100 797.720 ;
      RECT 0.140 799.680 16.100 799.960 ;
      RECT 0.140 801.920 16.100 802.200 ;
      RECT 0.140 804.160 16.100 804.440 ;
      RECT 0.140 806.400 16.100 806.680 ;
      RECT 0.140 808.640 16.100 808.920 ;
      RECT 0.140 810.880 16.100 811.160 ;
      RECT 0.140 813.120 16.100 813.400 ;
      RECT 0.140 815.360 16.100 815.640 ;
      RECT 0.140 817.600 16.100 817.880 ;
      RECT 0.140 819.840 16.100 820.120 ;
      RECT 0.140 822.080 16.100 822.360 ;
      RECT 0.140 824.320 16.100 824.600 ;
      RECT 0.140 826.560 16.100 826.840 ;
      RECT 0.140 828.800 16.100 829.080 ;
      RECT 0.140 831.040 16.100 831.320 ;
      RECT 0.140 833.280 16.100 833.560 ;
      RECT 0.140 835.520 16.100 835.800 ;
      RECT 0.140 837.760 16.100 838.040 ;
      RECT 0.140 840.000 16.100 840.280 ;
      RECT 0.140 842.240 16.100 842.520 ;
      RECT 0.140 844.480 16.100 844.760 ;
      RECT 0.140 846.720 16.100 847.000 ;
      RECT 0.140 848.960 16.100 849.240 ;
      RECT 0.140 851.200 16.100 851.480 ;
      RECT 0.140 853.440 16.100 853.720 ;
      RECT 0.140 855.680 16.100 855.960 ;
      RECT 0.140 857.920 16.100 858.200 ;
      RECT 0.140 860.160 16.100 860.440 ;
      RECT 0.140 862.400 16.100 862.680 ;
      RECT 0.140 864.640 16.100 864.920 ;
      RECT 0.140 866.880 16.100 867.160 ;
      RECT 0.140 869.120 16.100 869.400 ;
      RECT 0.140 871.360 16.100 871.640 ;
      RECT 0.140 873.600 16.100 873.880 ;
      RECT 0.140 875.840 16.100 876.120 ;
      RECT 0.140 878.080 16.100 878.360 ;
      RECT 0.140 880.320 16.100 880.600 ;
      RECT 0.140 882.560 16.100 882.840 ;
      RECT 0.140 884.800 16.100 885.080 ;
      RECT 0.140 887.040 16.100 887.320 ;
      RECT 0.140 889.280 16.100 889.560 ;
      RECT 0.140 891.520 16.100 891.800 ;
      RECT 0.140 893.760 16.100 894.040 ;
      RECT 0.140 896.000 16.100 896.280 ;
      RECT 0.140 898.240 16.100 898.520 ;
      RECT 0.140 900.480 16.100 900.760 ;
      RECT 0.140 902.720 16.100 903.000 ;
      RECT 0.140 904.960 16.100 905.240 ;
      RECT 0.140 907.200 16.100 907.480 ;
      RECT 0.140 909.440 16.100 909.720 ;
      RECT 0.140 911.680 16.100 911.960 ;
      RECT 0.140 913.920 16.100 914.200 ;
      RECT 0.140 916.160 16.100 916.440 ;
      RECT 0.140 918.400 16.100 918.680 ;
      RECT 0.140 920.640 16.100 920.920 ;
      RECT 0.140 922.880 16.100 923.160 ;
      RECT 0.140 925.120 16.100 925.400 ;
      RECT 0.140 927.360 16.100 927.640 ;
      RECT 0.140 929.600 16.100 929.880 ;
      RECT 0.140 931.840 16.100 932.120 ;
      RECT 0.140 934.080 16.100 934.360 ;
      RECT 0.140 936.320 16.100 936.600 ;
      RECT 0.140 938.560 16.100 938.840 ;
      RECT 0.140 940.800 16.100 941.080 ;
      RECT 0.140 943.040 16.100 943.320 ;
      RECT 0.140 945.280 16.100 945.560 ;
      RECT 0.140 947.520 16.100 947.800 ;
      RECT 0.140 949.760 16.100 950.040 ;
      RECT 0.140 952.000 16.100 952.280 ;
      RECT 0.140 954.240 16.100 954.520 ;
      RECT 0.140 956.480 16.100 956.760 ;
      RECT 0.140 958.720 16.100 959.000 ;
      RECT 0.140 960.960 16.100 961.240 ;
      RECT 0.140 963.200 16.100 963.480 ;
      RECT 0.140 965.440 16.100 965.720 ;
      RECT 0.140 967.680 16.100 967.960 ;
      RECT 0.140 969.920 16.100 970.200 ;
      RECT 0.140 972.160 16.100 972.440 ;
      RECT 0.140 974.400 16.100 974.680 ;
      RECT 0.140 976.640 16.100 976.920 ;
      RECT 0.140 978.880 16.100 979.160 ;
      RECT 0.140 981.120 16.100 981.400 ;
      RECT 0.140 983.360 16.100 983.640 ;
      RECT 0.140 985.600 16.100 985.880 ;
      RECT 0.140 987.840 16.100 988.120 ;
      RECT 0.140 990.080 16.100 990.360 ;
      RECT 0.140 992.320 16.100 992.600 ;
      RECT 0.140 994.560 16.100 994.840 ;
      RECT 0.140 996.800 16.100 997.080 ;
      RECT 0.140 999.040 16.100 999.320 ;
      RECT 0.140 1001.280 16.100 1001.560 ;
      RECT 0.140 1003.520 16.100 1003.800 ;
      RECT 0.140 1005.760 16.100 1006.040 ;
      RECT 0.140 1008.000 16.100 1008.280 ;
      RECT 0.140 1010.240 16.100 1010.520 ;
      RECT 0.140 1012.480 16.100 1012.760 ;
      RECT 0.140 1014.720 16.100 1015.000 ;
      RECT 0.140 1016.960 16.100 1017.240 ;
      RECT 0.140 1019.200 16.100 1019.480 ;
      RECT 0.140 1021.440 16.100 1021.720 ;
      RECT 0.140 1023.680 16.100 1023.960 ;
      RECT 0.140 1025.920 16.100 1026.200 ;
      RECT 0.140 1028.160 16.100 1028.440 ;
      RECT 0.140 1030.400 16.100 1030.680 ;
      RECT 0.140 1032.640 16.100 1032.920 ;
      RECT 0.140 1034.880 16.100 1035.160 ;
      RECT 0.140 1037.120 16.100 1037.400 ;
      RECT 0.140 1039.360 16.100 1039.640 ;
      RECT 0.140 1041.600 16.100 1041.880 ;
      RECT 0.140 1043.840 16.100 1044.120 ;
      RECT 0.140 1046.080 16.100 1046.360 ;
      RECT 0.140 1048.320 16.100 1048.600 ;
      RECT 0.140 1050.560 16.100 1050.840 ;
      RECT 0.140 1052.800 16.100 1053.080 ;
      RECT 0.140 1055.040 16.100 1055.320 ;
      RECT 0.140 1057.280 16.100 1057.560 ;
      RECT 0.140 1059.520 16.100 1059.800 ;
      RECT 0.140 1061.760 16.100 1062.040 ;
      RECT 0.140 1064.000 16.100 1064.280 ;
      RECT 0.140 1066.240 16.100 1066.520 ;
      RECT 0.140 1068.480 16.100 1068.760 ;
      RECT 0.140 1070.720 16.100 1071.000 ;
      RECT 0.140 1072.960 16.100 1073.240 ;
      RECT 0.140 1075.200 16.100 1075.480 ;
      RECT 0.140 1077.440 16.100 1077.720 ;
      RECT 0.140 1079.680 16.100 1079.960 ;
      RECT 0.140 1081.920 16.100 1082.200 ;
      RECT 0.140 1084.160 16.100 1084.440 ;
      RECT 0.140 1086.400 16.100 1086.680 ;
      RECT 0.140 1088.640 16.100 1088.920 ;
      RECT 0.140 1090.880 16.100 1091.160 ;
      RECT 0.140 1093.120 16.100 1093.400 ;
      RECT 0.140 1095.360 16.100 1095.640 ;
      RECT 0.140 1097.600 16.100 1097.880 ;
      RECT 0.140 1099.840 16.100 1100.120 ;
      RECT 0.140 1102.080 16.100 1102.360 ;
      RECT 0.140 1104.320 16.100 1104.600 ;
      RECT 0.140 1106.560 16.100 1106.840 ;
      RECT 0.140 1108.800 16.100 1109.080 ;
      RECT 0.140 1111.040 16.100 1111.320 ;
      RECT 0.140 1113.280 16.100 1113.560 ;
      RECT 0.140 1115.520 16.100 1115.800 ;
      RECT 0.140 1117.760 16.100 1118.040 ;
      RECT 0.140 1120.000 16.100 1120.280 ;
      RECT 0.140 1122.240 16.100 1122.520 ;
      RECT 0.140 1124.480 16.100 1124.760 ;
      RECT 0.140 1126.720 16.100 1127.000 ;
      RECT 0.140 1128.960 16.100 1129.240 ;
      RECT 0.140 1131.200 16.100 1131.480 ;
      RECT 0.140 1133.440 16.100 1133.720 ;
      RECT 0.140 1135.680 16.100 1135.960 ;
      RECT 0.140 1137.920 16.100 1138.200 ;
      RECT 0.140 1140.160 16.100 1140.440 ;
      RECT 0.140 1142.400 16.100 1142.680 ;
      RECT 0.140 1144.640 16.100 1144.920 ;
      RECT 0.140 1146.880 16.100 1147.160 ;
      RECT 0.140 1149.120 16.100 1149.400 ;
      RECT 0.140 1151.360 16.100 1151.640 ;
      RECT 0.140 1153.600 16.100 1153.880 ;
      RECT 0.140 1155.840 16.100 1156.120 ;
      RECT 0.140 1158.080 16.100 1158.360 ;
      RECT 0.140 1160.320 16.100 1160.600 ;
      RECT 0.140 1162.560 16.100 1162.840 ;
      RECT 0.140 1164.800 16.100 1165.080 ;
      RECT 0.140 1167.040 16.100 1167.320 ;
      RECT 0.140 1169.280 16.100 1169.560 ;
      RECT 0.140 1171.520 16.100 1171.800 ;
      RECT 0.140 1173.760 16.100 1174.040 ;
      RECT 0.140 1176.000 16.100 1176.280 ;
      RECT 0.140 1178.240 16.100 1178.520 ;
      RECT 0.140 1180.480 16.100 1180.760 ;
      RECT 0.140 1182.720 16.100 1183.000 ;
      RECT 0.140 1184.960 16.100 1185.240 ;
      RECT 0.140 1187.200 16.100 1187.480 ;
      RECT 0.140 1189.440 16.100 1189.720 ;
      RECT 0.140 1191.680 16.100 1191.960 ;
      RECT 0.140 1193.920 16.100 1194.200 ;
      RECT 0.140 1196.160 16.100 1196.440 ;
      RECT 0.140 1198.400 16.100 1198.680 ;
      RECT 0.140 1200.640 16.100 1200.920 ;
      RECT 0.140 1202.880 16.100 1203.160 ;
      RECT 0.140 1205.120 16.100 1205.400 ;
      RECT 0.140 1207.360 16.100 1207.640 ;
      RECT 0.140 1209.600 16.100 1209.880 ;
      RECT 0.140 1211.840 16.100 1212.120 ;
      RECT 0.140 1214.080 16.100 1214.360 ;
      RECT 0.140 1216.320 16.100 1216.600 ;
      RECT 0.140 1218.560 16.100 1218.840 ;
      RECT 0.140 1220.800 16.100 1221.080 ;
      RECT 0.140 1223.040 16.100 1223.320 ;
      RECT 0.140 1225.280 16.100 1225.560 ;
      RECT 0.140 1227.520 16.100 1227.800 ;
      RECT 0.140 1229.760 16.100 1230.040 ;
      RECT 0.140 1232.000 16.100 1232.280 ;
      RECT 0.140 1234.240 16.100 1234.520 ;
      RECT 0.140 1236.480 16.100 1236.760 ;
      RECT 0.140 1238.720 16.100 1239.000 ;
      RECT 0.140 1240.960 16.100 1241.240 ;
      RECT 0.140 1243.200 16.100 1243.480 ;
      RECT 0.140 1245.440 16.100 1245.720 ;
      RECT 0.140 1247.680 16.100 1247.960 ;
      RECT 0.140 1249.920 16.100 1250.200 ;
      RECT 0.140 1252.160 16.100 1252.440 ;
      RECT 0.140 1254.400 16.100 1254.680 ;
      RECT 0.140 1256.640 16.100 1256.920 ;
      RECT 0.140 1258.880 16.100 1259.160 ;
      RECT 0.140 1261.120 16.100 1261.400 ;
      RECT 0.140 1263.360 16.100 1263.640 ;
      RECT 0.140 1265.600 16.100 1265.880 ;
      RECT 0.140 1267.840 16.100 1268.120 ;
      RECT 0.140 1270.080 16.100 1270.360 ;
      RECT 0.140 1272.320 16.100 1272.600 ;
      RECT 0.140 1274.560 16.100 1274.840 ;
      RECT 0.140 1276.800 16.100 1277.080 ;
      RECT 0.140 1279.040 16.100 1279.320 ;
      RECT 0.140 1281.280 16.100 1281.560 ;
      RECT 0.140 1283.520 16.100 1283.800 ;
      RECT 0.140 1285.760 16.100 1286.040 ;
      RECT 0.140 1288.000 16.100 1288.280 ;
      RECT 0.140 1290.240 16.100 1290.520 ;
      RECT 0.140 1292.480 16.100 1292.760 ;
      RECT 0.140 1294.720 16.100 1295.000 ;
      RECT 0.140 1296.960 16.100 1297.240 ;
      RECT 0.140 1299.200 16.100 1299.480 ;
      RECT 0.140 1301.440 16.100 1301.720 ;
      RECT 0.140 1303.680 16.100 1303.960 ;
      RECT 0.140 1305.920 16.100 1306.200 ;
      RECT 0.140 1308.160 16.100 1308.440 ;
      RECT 0.140 1310.400 16.100 1310.680 ;
      RECT 0.140 1312.640 16.100 1312.920 ;
      RECT 0.140 1314.880 16.100 1315.160 ;
      RECT 0.140 1317.120 16.100 1317.400 ;
      RECT 0.140 1319.360 16.100 1319.640 ;
      RECT 0.140 1321.600 16.100 1321.880 ;
      RECT 0.140 1323.840 16.100 1324.120 ;
      RECT 0.140 1326.080 16.100 1326.360 ;
      RECT 0.140 1328.320 16.100 1328.600 ;
      RECT 0.140 1330.560 16.100 1330.840 ;
      RECT 0.140 1332.800 16.100 1333.080 ;
      RECT 0.140 1335.040 16.100 1335.320 ;
      RECT 0.140 1337.280 16.100 1337.560 ;
      RECT 0.140 1339.520 16.100 1339.800 ;
      RECT 0.140 1341.760 16.100 1342.040 ;
      RECT 0.140 1344.000 16.100 1344.280 ;
      RECT 0.140 1346.240 16.100 1346.520 ;
      RECT 0.140 1348.480 16.100 1348.760 ;
      RECT 0.140 1350.720 16.100 1351.000 ;
      RECT 0.140 1352.960 16.100 1353.240 ;
      RECT 0.140 1355.200 16.100 1355.480 ;
      RECT 0.140 1357.440 16.100 1357.720 ;
      RECT 0.140 1359.680 16.100 1359.960 ;
      RECT 0.140 1361.920 16.100 1362.200 ;
      RECT 0.140 1364.160 16.100 1364.440 ;
      RECT 0.140 1366.400 16.100 1366.680 ;
      RECT 0.140 1368.640 16.100 1368.920 ;
      RECT 0.140 1370.880 16.100 1371.160 ;
      RECT 0.140 1373.120 16.100 1373.400 ;
      RECT 0.140 1375.360 16.100 1375.640 ;
      RECT 0.140 1377.600 16.100 1377.880 ;
      RECT 0.140 1379.840 16.100 1380.120 ;
      RECT 0.140 1382.080 16.100 1382.360 ;
      RECT 0.140 1384.320 16.100 1384.600 ;
      RECT 0.140 1386.560 16.100 1386.840 ;
      RECT 0.140 1388.800 16.100 1389.080 ;
      RECT 0.140 1391.040 16.100 1391.320 ;
      RECT 0.140 1393.280 16.100 1393.560 ;
      RECT 0.140 1395.520 16.100 1395.800 ;
      RECT 0.140 1397.760 16.100 1398.040 ;
      RECT 0.140 1400.000 16.100 1400.280 ;
      RECT 0.140 1402.240 16.100 1402.520 ;
      RECT 0.140 1404.480 16.100 1404.760 ;
      RECT 0.140 1406.720 16.100 1407.000 ;
      RECT 0.140 1408.960 16.100 1409.240 ;
      RECT 0.140 1411.200 16.100 1411.480 ;
      RECT 0.140 1413.440 16.100 1413.720 ;
      RECT 0.140 1415.680 16.100 1415.960 ;
      RECT 0.140 1417.920 16.100 1418.200 ;
      RECT 0.140 1420.160 16.100 1420.440 ;
      RECT 0.140 1422.400 16.100 1422.680 ;
      RECT 0.140 1424.640 16.100 1424.920 ;
      RECT 0.140 1426.880 16.100 1427.160 ;
      RECT 0.140 1429.120 16.100 1429.400 ;
      RECT 0.140 1431.360 16.100 1431.640 ;
      RECT 0.140 1433.600 16.100 1433.880 ;
      RECT 0.140 1435.840 16.100 1436.120 ;
      RECT 0.140 1438.080 16.100 1438.360 ;
      RECT 0.140 1440.320 16.100 1440.600 ;
      RECT 0.140 1442.560 16.100 1442.840 ;
      RECT 0.140 1444.800 16.100 1445.080 ;
      RECT 0.140 1447.040 16.100 1447.320 ;
      RECT 0.140 1449.280 16.100 1449.560 ;
      RECT 0.140 1451.520 16.100 1451.800 ;
      RECT 0.140 1453.760 16.100 1454.040 ;
      RECT 0.140 1456.000 16.100 1456.280 ;
      RECT 0.140 1458.240 16.100 1458.520 ;
      RECT 0.140 1460.480 16.100 1460.760 ;
      RECT 0.140 1462.720 16.100 1463.000 ;
      RECT 0.140 1464.960 16.100 1465.240 ;
      RECT 0.140 1467.200 16.100 1467.480 ;
      RECT 0.140 1469.440 16.100 1469.720 ;
      RECT 0.140 1471.680 16.100 1471.960 ;
      RECT 0.140 1473.920 16.100 1474.200 ;
      RECT 0.140 1476.160 16.100 1476.440 ;
      RECT 0.140 1478.400 16.100 1478.680 ;
      RECT 0.140 1480.640 16.100 1480.920 ;
      RECT 0.140 1482.880 16.100 1483.160 ;
      RECT 0.140 1485.120 16.100 1485.400 ;
      RECT 0.140 1487.360 16.100 1487.640 ;
      RECT 0.140 1489.600 16.100 1489.880 ;
      RECT 0.140 1491.840 16.100 1492.120 ;
      RECT 0.140 1494.080 16.100 1494.360 ;
      RECT 0.140 1496.320 16.100 1496.600 ;
      RECT 0.140 1498.560 16.100 1498.840 ;
      RECT 0.140 1500.800 16.100 1501.080 ;
      RECT 0.140 1503.040 16.100 1503.320 ;
      RECT 0.140 1505.280 16.100 1505.560 ;
      RECT 0.140 1507.520 16.100 1507.800 ;
      RECT 0.140 1509.760 16.100 1510.040 ;
      RECT 0.140 1512.000 16.100 1512.280 ;
      RECT 0.140 1514.240 16.100 1514.520 ;
      RECT 0.140 1516.480 16.100 1516.760 ;
      RECT 0.140 1518.720 16.100 1519.000 ;
      RECT 0.140 1520.960 16.100 1521.240 ;
      RECT 0.140 1523.200 16.100 1523.480 ;
      RECT 0.140 1525.440 16.100 1525.720 ;
      RECT 0.140 1527.680 16.100 1527.960 ;
      RECT 0.140 1529.920 16.100 1530.200 ;
      RECT 0.140 1532.160 16.100 1532.440 ;
      RECT 0.140 1534.400 16.100 1534.680 ;
      RECT 0.140 1536.640 16.100 1536.920 ;
      RECT 0.140 1538.880 16.100 1539.160 ;
      RECT 0.140 1541.120 16.100 1541.400 ;
      RECT 0.140 1543.360 16.100 1543.640 ;
      RECT 0.140 1545.600 16.100 1545.880 ;
      RECT 0.140 1547.840 16.100 1548.120 ;
      RECT 0.140 1550.080 16.100 1550.360 ;
      RECT 0.140 1552.320 16.100 1552.600 ;
      RECT 0.140 1554.560 16.100 1554.840 ;
      RECT 0.140 1556.800 16.100 1557.080 ;
      RECT 0.140 1559.040 16.100 1559.320 ;
      RECT 0.140 1561.280 16.100 1561.560 ;
      RECT 0.140 1563.520 16.100 1563.800 ;
      RECT 0.140 1565.760 16.100 1566.040 ;
      RECT 0.140 1568.000 16.100 1568.280 ;
      RECT 0.140 1570.240 16.100 1570.520 ;
      RECT 0.140 1572.480 16.100 1572.760 ;
      RECT 0.140 1574.720 16.100 1575.000 ;
      RECT 0.140 1576.960 16.100 1577.240 ;
      RECT 0.140 1579.200 16.100 1579.480 ;
      RECT 0.140 1581.440 16.100 1581.720 ;
      RECT 0.140 1583.680 16.100 1583.960 ;
      RECT 0.140 1585.920 16.100 1586.200 ;
      RECT 0.140 1588.160 16.100 1588.440 ;
      RECT 0.140 1590.400 16.100 1590.680 ;
      RECT 0.140 1592.640 16.100 1592.920 ;
      RECT 0.140 1594.880 16.100 1595.160 ;
      RECT 0.140 1597.120 16.100 1597.400 ;
      RECT 0.140 1599.360 16.100 1599.640 ;
      RECT 0.140 1601.600 16.100 1601.880 ;
      RECT 0.140 1603.840 16.100 1604.120 ;
      RECT 0.140 1606.080 16.100 1606.360 ;
      RECT 0.140 1608.320 16.100 1608.600 ;
      RECT 0.140 1610.560 16.100 1610.840 ;
      RECT 0.140 1612.800 16.100 1613.080 ;
      RECT 0.140 1615.040 16.100 1615.320 ;
      RECT 0.140 1617.280 16.100 1617.560 ;
      RECT 0.140 1619.520 16.100 1619.800 ;
      RECT 0.140 1621.760 16.100 1622.040 ;
      RECT 0.140 1624.000 16.100 1624.280 ;
      RECT 0.140 1626.240 16.100 1626.520 ;
      RECT 0.140 1628.480 16.100 1628.760 ;
      RECT 0.140 1630.720 16.100 1631.000 ;
      RECT 0.140 1632.960 16.100 1633.240 ;
      RECT 0.140 1635.200 16.100 1635.480 ;
      RECT 0.140 1637.440 16.100 1637.720 ;
      RECT 0.140 1639.680 16.100 1639.960 ;
      RECT 0.140 1641.920 16.100 1642.200 ;
      RECT 0.140 1644.160 16.100 1644.440 ;
      RECT 0.140 1646.400 16.100 1646.680 ;
      RECT 0.140 1648.640 16.100 1648.920 ;
      RECT 0.140 1650.880 16.100 1651.160 ;
      RECT 0.140 1653.120 16.100 1653.400 ;
      RECT 0.140 1655.360 16.100 1655.640 ;
      RECT 0.140 1657.600 16.100 1657.880 ;
      RECT 0.140 1659.840 16.100 1660.120 ;
      RECT 0.140 1662.080 16.100 1662.360 ;
      RECT 0.140 1664.320 16.100 1664.600 ;
      RECT 0.140 1666.560 16.100 1666.840 ;
      RECT 0.140 1668.800 16.100 1669.080 ;
      RECT 0.140 1671.040 16.100 1671.320 ;
      RECT 0.140 1673.280 16.100 1673.560 ;
      RECT 0.140 1675.520 16.100 1675.800 ;
      RECT 0.140 1677.760 16.100 1678.040 ;
      RECT 0.140 1680.000 16.100 1680.280 ;
      RECT 0.140 1682.240 16.100 1682.520 ;
      RECT 0.140 1684.480 16.100 1684.760 ;
      RECT 0.140 1686.720 16.100 1687.000 ;
      RECT 0.140 1688.960 16.100 1689.240 ;
      RECT 0.140 1691.200 16.100 1691.480 ;
      RECT 0.140 1693.440 16.100 1693.720 ;
      RECT 0.140 1695.680 16.100 1695.960 ;
      RECT 0.140 1697.920 16.100 1698.200 ;
      RECT 0.140 1700.160 16.100 1700.440 ;
      RECT 0.140 1702.400 16.100 1702.680 ;
      RECT 0.140 1704.640 16.100 1704.920 ;
      RECT 0.140 1706.880 16.100 1707.160 ;
      RECT 0.140 1709.120 16.100 1709.400 ;
      RECT 0.140 1711.360 16.100 1711.640 ;
      RECT 0.140 1713.600 16.100 1713.880 ;
      RECT 0.140 1715.840 16.100 1716.120 ;
      RECT 0.140 1718.080 16.100 1718.360 ;
      RECT 0.140 1720.320 16.100 1720.600 ;
      RECT 0.140 1722.560 16.100 1722.840 ;
      RECT 0.140 1724.800 16.100 1725.080 ;
      RECT 0.140 1727.040 16.100 1727.320 ;
      RECT 0.140 1729.280 16.100 1729.560 ;
      RECT 0.140 1731.520 16.100 1731.800 ;
      RECT 0.140 1733.760 16.100 1734.040 ;
      RECT 0.140 1736.000 16.100 1736.280 ;
      RECT 0.140 1738.240 16.100 1738.520 ;
      RECT 0.140 1740.480 16.100 1740.760 ;
      RECT 0.140 1742.720 16.100 1743.000 ;
      RECT 0.140 1744.960 16.100 1745.240 ;
      RECT 0.140 1747.200 16.100 1747.480 ;
      RECT 0.140 1749.440 16.100 1749.720 ;
      RECT 0.140 1751.680 16.100 1751.960 ;
      RECT 0.140 1753.920 16.100 1754.200 ;
      RECT 0.140 1756.160 16.100 1756.440 ;
      RECT 0.140 1758.400 16.100 1758.680 ;
      RECT 0.140 1760.640 16.100 1760.920 ;
      RECT 0.140 1762.880 16.100 1763.160 ;
      RECT 0.140 1765.120 16.100 1765.400 ;
      RECT 0.140 1767.360 16.100 1767.640 ;
      RECT 0.140 1769.600 16.100 1769.880 ;
      RECT 0.140 1771.840 16.100 1772.120 ;
      RECT 0.140 1774.080 16.100 1774.360 ;
      RECT 0.140 1776.320 16.100 1776.600 ;
      RECT 0.140 1778.560 16.100 1778.840 ;
      RECT 0.140 1780.800 16.100 1781.080 ;
      RECT 0.140 1783.040 16.100 1783.320 ;
      RECT 0.140 1785.280 16.100 1785.560 ;
      RECT 0.140 1787.520 16.100 1787.800 ;
      RECT 0.140 1789.760 16.100 1790.040 ;
      RECT 0.140 1792.000 16.100 1792.280 ;
      RECT 0.140 1794.240 16.100 1794.520 ;
      RECT 0.140 1796.480 16.100 1796.760 ;
      RECT 0.140 1798.720 16.100 1799.000 ;
      RECT 0.140 1800.960 16.100 1801.240 ;
      RECT 0.140 1803.200 16.100 1803.480 ;
      RECT 0.140 1805.440 16.100 1805.720 ;
      RECT 0.140 1807.680 16.100 1807.960 ;
      RECT 0.140 1809.920 16.100 1810.200 ;
      RECT 0.140 1812.160 16.100 1812.440 ;
      RECT 0.140 1814.400 16.100 1814.680 ;
      RECT 0.140 1816.640 16.100 1816.920 ;
      RECT 0.140 1818.880 16.100 1819.160 ;
      RECT 0.140 1821.120 16.100 1821.400 ;
      RECT 0.140 1823.360 16.100 1823.640 ;
      RECT 0.140 1825.600 16.100 1825.880 ;
      RECT 0.140 1827.840 16.100 1828.120 ;
      RECT 0.140 1830.080 16.100 1830.360 ;
      RECT 0.140 1832.320 16.100 1832.600 ;
      RECT 0.140 1834.560 16.100 1834.840 ;
      RECT 0.140 1836.800 16.100 1837.080 ;
      RECT 0.140 1839.040 16.100 1839.320 ;
      RECT 0.140 1841.280 16.100 1841.560 ;
      RECT 0.140 1843.520 16.100 1843.800 ;
      RECT 0.140 1845.760 16.100 1846.040 ;
      RECT 0.140 1848.000 16.100 1848.280 ;
      RECT 0.140 1850.240 16.100 1850.520 ;
      RECT 0.140 1852.480 16.100 1852.760 ;
      RECT 0.140 1854.720 16.100 1855.000 ;
      RECT 0.140 1856.960 16.100 1857.240 ;
      RECT 0.140 1859.200 16.100 1859.480 ;
      RECT 0.140 1861.440 16.100 1861.720 ;
      RECT 0.140 1863.680 16.100 1863.960 ;
      RECT 0.140 1865.920 16.100 1866.200 ;
      RECT 0.140 1868.160 16.100 1868.440 ;
      RECT 0.140 1870.400 16.100 1870.680 ;
      RECT 0.140 1872.640 16.100 1872.920 ;
      RECT 0.140 1874.880 16.100 1875.160 ;
      RECT 0.140 1877.120 16.100 1877.400 ;
      RECT 0.140 1879.360 16.100 1879.640 ;
      RECT 0.140 1881.600 16.100 1881.880 ;
      RECT 0.140 1883.840 16.100 1884.120 ;
      RECT 0.140 1886.080 16.100 1886.360 ;
      RECT 0.140 1888.320 16.100 1888.600 ;
      RECT 0.140 1890.560 16.100 1890.840 ;
      RECT 0.140 1892.800 16.100 1893.080 ;
      RECT 0.140 1895.040 16.100 1895.320 ;
      RECT 0.140 1897.280 16.100 1897.560 ;
      RECT 0.140 1899.520 16.100 1899.800 ;
      RECT 0.140 1901.760 16.100 1902.040 ;
      RECT 0.140 1904.000 16.100 1904.280 ;
      RECT 0.140 1906.240 16.100 1906.520 ;
      RECT 0.140 1908.480 16.100 1908.760 ;
      RECT 0.140 1910.720 16.100 1911.000 ;
      RECT 0.140 1912.960 16.100 1913.240 ;
      RECT 0.140 1915.200 16.100 1915.480 ;
      RECT 0.140 1917.440 16.100 1917.720 ;
      RECT 0.140 1919.680 16.100 1919.960 ;
      RECT 0.140 1921.920 16.100 1922.200 ;
      RECT 0.140 1924.160 16.100 1924.440 ;
      RECT 0.140 1926.400 16.100 1926.680 ;
      RECT 0.140 1928.640 16.100 1928.920 ;
      RECT 0.140 1930.880 16.100 1931.160 ;
      RECT 0.140 1933.120 16.100 1933.400 ;
      RECT 0.140 1935.360 16.100 1935.640 ;
      RECT 0.140 1937.600 16.100 1937.880 ;
      RECT 0.140 1939.840 16.100 1940.120 ;
      RECT 0.140 1942.080 16.100 1942.360 ;
      RECT 0.140 1944.320 16.100 1944.600 ;
      RECT 0.140 1946.560 16.100 1946.840 ;
      RECT 0.140 1948.800 16.100 1949.080 ;
      RECT 0.140 1951.040 16.100 1951.320 ;
      RECT 0.140 1953.280 16.100 1953.560 ;
      RECT 0.140 1955.520 16.100 1955.800 ;
      RECT 0.140 1957.760 16.100 1958.040 ;
      RECT 0.140 1960.000 16.100 1960.280 ;
      RECT 0.140 1962.240 16.100 1962.520 ;
      RECT 0.140 1964.480 16.100 1964.760 ;
      RECT 0.140 1966.720 16.100 1967.000 ;
      RECT 0.140 1968.960 16.100 1969.240 ;
      RECT 0.140 1971.200 16.100 1971.480 ;
      RECT 0.140 1973.440 16.100 1973.720 ;
      RECT 0.140 1975.680 16.100 1975.960 ;
      RECT 0.140 1977.920 16.100 1978.200 ;
      RECT 0.140 1980.160 16.100 1980.440 ;
      RECT 0.140 1982.400 16.100 1982.680 ;
      RECT 0.140 1984.640 16.100 1984.920 ;
      RECT 0.140 1986.880 16.100 1987.160 ;
      RECT 0.140 1989.120 16.100 1989.400 ;
      RECT 0.140 1991.360 16.100 1991.640 ;
      RECT 0.140 1993.600 16.100 1993.880 ;
      RECT 0.140 1995.840 16.100 1996.120 ;
      RECT 0.140 1998.080 16.100 1998.360 ;
      RECT 0.140 2000.320 16.100 2000.600 ;
      RECT 0.140 2002.560 16.100 2002.840 ;
      RECT 0.140 2004.800 16.100 2005.080 ;
      RECT 0.140 2007.040 16.100 2007.320 ;
      RECT 0.140 2009.280 16.100 2009.560 ;
      RECT 0.140 2011.520 16.100 2011.800 ;
      RECT 0.140 2013.760 16.100 2014.040 ;
      RECT 0.140 2016.000 16.100 2016.280 ;
      RECT 0.140 2018.240 16.100 2018.520 ;
      RECT 0.140 2020.480 16.100 2020.760 ;
      RECT 0.140 2022.720 16.100 2023.000 ;
      RECT 0.140 2024.960 16.100 2025.240 ;
      RECT 0.140 2027.200 16.100 2027.480 ;
      RECT 0.140 2029.440 16.100 2029.720 ;
      RECT 0.140 2031.680 16.100 2031.960 ;
      RECT 0.140 2033.920 16.100 2034.200 ;
      RECT 0.140 2036.160 16.100 2036.440 ;
      RECT 0.140 2038.400 16.100 2038.680 ;
      RECT 0.140 2040.640 16.100 2040.920 ;
      RECT 0.140 2042.880 16.100 2043.160 ;
      RECT 0.140 2045.120 16.100 2045.400 ;
      RECT 0.140 2047.360 16.100 2047.640 ;
      RECT 0.140 2049.600 16.100 2049.880 ;
      RECT 0.140 2051.840 16.100 2052.120 ;
      RECT 0.140 2054.080 16.100 2054.360 ;
      RECT 0.140 2056.320 16.100 2056.600 ;
      RECT 0.140 2058.560 16.100 2058.840 ;
      RECT 0.140 2060.800 16.100 2061.080 ;
      RECT 0.140 2063.040 16.100 2063.320 ;
      RECT 0.140 2065.280 16.100 2065.560 ;
      RECT 0.140 2067.520 16.100 2067.800 ;
      RECT 0.140 2069.760 16.100 2070.040 ;
      RECT 0.140 2072.000 16.100 2072.280 ;
      RECT 0.140 2074.240 16.100 2074.520 ;
      RECT 0.140 2076.480 16.100 2076.760 ;
      RECT 0.140 2078.720 16.100 2079.000 ;
      RECT 0.140 2080.960 16.100 2081.240 ;
      RECT 0.140 2083.200 16.100 2083.480 ;
      RECT 0.140 2085.440 16.100 2085.720 ;
      RECT 0.140 2087.680 16.100 2087.960 ;
      RECT 0.140 2089.920 16.100 2090.200 ;
      RECT 0.140 2092.160 16.100 2092.440 ;
      RECT 0.140 2094.400 16.100 2094.680 ;
      RECT 0.140 2096.640 16.100 2096.920 ;
      RECT 0.140 2098.880 16.100 2099.160 ;
      RECT 0.140 2101.120 16.100 2101.400 ;
      RECT 0.140 2103.360 16.100 2103.640 ;
      RECT 0.140 2105.600 16.100 2105.880 ;
      RECT 0.140 2107.840 16.100 2108.120 ;
      RECT 0.140 2110.080 16.100 2110.360 ;
      RECT 0.140 2112.320 16.100 2112.600 ;
      RECT 0.140 2114.560 16.100 2114.840 ;
      RECT 0.140 2116.800 16.100 2117.080 ;
      RECT 0.140 2119.040 16.100 2119.320 ;
      RECT 0.140 2121.280 16.100 2121.560 ;
      RECT 0.140 2123.520 16.100 2123.800 ;
      RECT 0.140 2125.760 16.100 2126.040 ;
      RECT 0.140 2128.000 16.100 2128.280 ;
      RECT 0.140 2130.240 16.100 2130.520 ;
      RECT 0.140 2132.480 16.100 2132.760 ;
      RECT 0.140 2134.720 16.100 2135.000 ;
      RECT 0.140 2136.960 16.100 2137.240 ;
      RECT 0.140 2139.200 16.100 2139.480 ;
      RECT 0.140 2141.440 16.100 2141.720 ;
      RECT 0.140 2143.680 16.100 2143.960 ;
      RECT 0.140 2145.920 16.100 2146.200 ;
      RECT 0.140 2148.160 16.100 2148.440 ;
      RECT 0.140 2150.400 16.100 2150.680 ;
      RECT 0.140 2152.640 16.100 2152.920 ;
      RECT 0.140 2154.880 16.100 2155.160 ;
      RECT 0.140 2157.120 16.100 2157.400 ;
      RECT 0.140 2159.360 16.100 2159.640 ;
      RECT 0.140 2161.600 16.100 2161.880 ;
      RECT 0.140 2163.840 16.100 2164.120 ;
      RECT 0.140 2166.080 16.100 2166.360 ;
      RECT 0.140 2168.320 16.100 2168.600 ;
      RECT 0.140 2170.560 16.100 2170.840 ;
      RECT 0.140 2172.800 16.100 2173.080 ;
      RECT 0.140 2175.040 16.100 2175.320 ;
      RECT 0.140 2177.280 16.100 2177.560 ;
      RECT 0.140 2179.520 16.100 2179.800 ;
      RECT 0.140 2181.760 16.100 2182.040 ;
      RECT 0.140 2184.000 16.100 2184.280 ;
      RECT 0.140 2186.240 16.100 2186.520 ;
      RECT 0.140 2188.480 16.100 2188.760 ;
      RECT 0.140 2190.720 16.100 2191.000 ;
      RECT 0.140 2192.960 16.100 2193.240 ;
      RECT 0.140 2195.200 16.100 2195.480 ;
      RECT 0.140 2197.440 16.100 2197.720 ;
      RECT 0.140 2199.680 16.100 2199.960 ;
      RECT 0.140 2201.920 16.100 2202.200 ;
      RECT 0.140 2204.160 16.100 2204.440 ;
      RECT 0.140 2206.400 16.100 2206.680 ;
      RECT 0.140 2208.640 16.100 2208.920 ;
      RECT 0.140 2210.880 16.100 2211.160 ;
      RECT 0.140 2213.120 16.100 2213.400 ;
      RECT 0.140 2215.360 16.100 2215.640 ;
      RECT 0.140 2217.600 16.100 2217.880 ;
      RECT 0.140 2219.840 16.100 2220.120 ;
      RECT 0.140 2222.080 16.100 2222.360 ;
      RECT 0.140 2224.320 16.100 2224.600 ;
      RECT 0.140 2226.560 16.100 2226.840 ;
      RECT 0.140 2228.800 16.100 2229.080 ;
      RECT 0.140 2231.040 16.100 2231.320 ;
      RECT 0.140 2233.280 16.100 2233.560 ;
      RECT 0.140 2235.520 16.100 2235.800 ;
      RECT 0.140 2237.760 16.100 2238.040 ;
      RECT 0.140 2240.000 16.100 2240.280 ;
      RECT 0.140 2242.240 16.100 2242.520 ;
      RECT 0.140 2244.480 16.100 2244.760 ;
      RECT 0.140 2246.720 16.100 2247.000 ;
      RECT 0.140 2248.960 16.100 2249.240 ;
      RECT 0.140 2251.200 16.100 2251.480 ;
      RECT 0.140 2253.440 16.100 2253.720 ;
      RECT 0.140 2255.680 16.100 2255.960 ;
      RECT 0.140 2257.920 16.100 2258.200 ;
      RECT 0.140 2260.160 16.100 2260.440 ;
      RECT 0.140 2262.400 16.100 2262.680 ;
      RECT 0.140 2264.640 16.100 2264.920 ;
      RECT 0.140 2266.880 16.100 2267.160 ;
      RECT 0.140 2269.120 16.100 2269.400 ;
      RECT 0.140 2271.360 16.100 2271.640 ;
      RECT 0.140 2273.600 16.100 2273.880 ;
      RECT 0.140 2275.840 16.100 2276.120 ;
      RECT 0.140 2278.080 16.100 2278.360 ;
      RECT 0.140 2280.320 16.100 2280.600 ;
      RECT 0.140 2282.560 16.100 2282.840 ;
      RECT 0.140 2284.800 16.100 2285.080 ;
      RECT 0.140 2287.040 16.100 2287.320 ;
      RECT 0.140 2289.280 16.100 2289.560 ;
      RECT 0.140 2291.520 16.100 2291.800 ;
      RECT 0.140 2293.760 16.100 2294.040 ;
      RECT 0.140 2296.000 16.100 2296.280 ;
      RECT 0.140 2298.240 16.100 2298.520 ;
      RECT 0.140 2300.480 16.100 2300.760 ;
      RECT 0.140 2302.720 16.100 2303.000 ;
      RECT 0.140 2304.960 16.100 2305.240 ;
      RECT 0.140 2307.200 16.100 2307.480 ;
      RECT 0.140 2309.440 16.100 2309.720 ;
      RECT 0.140 2311.680 16.100 2311.960 ;
      RECT 0.140 2313.920 16.100 2314.200 ;
      RECT 0.140 2316.160 16.100 2316.440 ;
      RECT 0.140 2318.400 16.100 2318.680 ;
      RECT 0.140 2320.640 16.100 2320.920 ;
      RECT 0.140 2322.880 16.100 2323.160 ;
      RECT 0.140 2325.120 16.100 2325.400 ;
      RECT 0.140 2327.360 16.100 2327.640 ;
      RECT 0.140 2329.600 16.100 2329.880 ;
      RECT 0.140 2331.840 16.100 2332.120 ;
      RECT 0.140 2334.080 16.100 2334.360 ;
      RECT 0.140 2336.320 16.100 2336.600 ;
      RECT 0.140 2338.560 16.100 2338.840 ;
      RECT 0.140 2340.800 16.100 2341.080 ;
      RECT 0.140 2343.040 16.100 2343.320 ;
      RECT 0.140 2345.280 16.100 2345.560 ;
      RECT 0.140 2347.520 16.100 2347.800 ;
      RECT 0.140 2349.760 16.100 2350.040 ;
      RECT 0.140 2352.000 16.100 2352.280 ;
      RECT 0.140 2354.240 16.100 2354.520 ;
      RECT 0.140 2356.480 16.100 2356.760 ;
      RECT 0.140 2358.720 16.100 2359.000 ;
      RECT 0.140 2360.960 16.100 2361.240 ;
      RECT 0.140 2363.200 16.100 2363.480 ;
      RECT 0.140 2365.440 16.100 2365.720 ;
      RECT 0.140 2367.680 16.100 2367.960 ;
      RECT 0.140 2369.920 16.100 2370.200 ;
      RECT 0.140 2372.160 16.100 2372.440 ;
      RECT 0.140 2374.400 16.100 2374.680 ;
      RECT 0.140 2376.640 16.100 2376.920 ;
      RECT 0.140 2378.880 16.100 2379.160 ;
      RECT 0.140 2381.120 16.100 2381.400 ;
      RECT 0.140 2383.360 16.100 2383.640 ;
      RECT 0.140 2385.600 16.100 2385.880 ;
      RECT 0.140 2387.840 16.100 2388.120 ;
      RECT 0.140 2390.080 16.100 2390.360 ;
      RECT 0.140 2392.320 16.100 2392.600 ;
      RECT 0.140 2394.560 16.100 2394.840 ;
      RECT 0.140 2396.800 16.100 2397.080 ;
      RECT 0.140 2399.040 16.100 2399.320 ;
      RECT 0.140 2401.280 16.100 2401.560 ;
      RECT 0.140 2403.520 16.100 2403.800 ;
      RECT 0.140 2405.760 16.100 2406.040 ;
      RECT 0.140 2408.000 16.100 2408.280 ;
      RECT 0.140 2410.240 16.100 2410.520 ;
      RECT 0.140 2412.480 16.100 2412.760 ;
      RECT 0.140 2414.720 16.100 2415.000 ;
      RECT 0.140 2416.960 16.100 2417.240 ;
      RECT 0.140 2419.200 16.100 2419.480 ;
      RECT 0.140 2421.440 16.100 2421.720 ;
      RECT 0.140 2423.680 16.100 2423.960 ;
      RECT 0.140 2425.920 16.100 2426.200 ;
      RECT 0.140 2428.160 16.100 2428.440 ;
      RECT 0.140 2430.400 16.100 2430.680 ;
      RECT 0.140 2432.640 16.100 2432.920 ;
      RECT 0.140 2434.880 16.100 2435.160 ;
      RECT 0.140 2437.120 16.100 2437.400 ;
      RECT 0.140 2439.360 16.100 2439.640 ;
      RECT 0.140 2441.600 16.100 2441.880 ;
      RECT 0.140 2443.840 16.100 2444.120 ;
      RECT 0.140 2446.080 16.100 2446.360 ;
      RECT 0.140 2448.320 16.100 2448.600 ;
      RECT 0.140 2450.560 16.100 2450.840 ;
      RECT 0.140 2452.800 16.100 2453.080 ;
      RECT 0.140 2455.040 16.100 2455.320 ;
      RECT 0.140 2457.280 16.100 2457.560 ;
      RECT 0.140 2459.520 16.100 2459.800 ;
      RECT 0.140 2461.760 16.100 2462.040 ;
      RECT 0.140 2464.000 16.100 2464.280 ;
      RECT 0.140 2466.240 16.100 2466.520 ;
      RECT 0.140 2468.480 16.100 2468.760 ;
      RECT 0.140 2470.720 16.100 2471.000 ;
      RECT 0.140 2472.960 16.100 2473.240 ;
      RECT 0.140 2475.200 16.100 2475.480 ;
      RECT 0.140 2477.440 16.100 2477.720 ;
      RECT 0.140 2479.680 16.100 2479.960 ;
      RECT 0.140 2481.920 16.100 2482.200 ;
      RECT 0.140 2484.160 16.100 2484.440 ;
      RECT 0.140 2486.400 16.100 2486.680 ;
      RECT 0.140 2488.640 16.100 2488.920 ;
      RECT 0.140 2490.880 16.100 2491.160 ;
      RECT 0.140 2493.120 16.100 2493.400 ;
      RECT 0.140 2495.360 16.100 2495.640 ;
      RECT 0.140 2497.600 16.100 2497.880 ;
      RECT 0.140 2499.840 16.100 2500.120 ;
      RECT 0.140 2502.080 16.100 2502.360 ;
      RECT 0.140 2504.320 16.100 2504.600 ;
      RECT 0.140 2506.560 16.100 2506.840 ;
      RECT 0.140 2508.800 16.100 2509.080 ;
      RECT 0.140 2511.040 16.100 2511.320 ;
      RECT 0.140 2513.280 16.100 2513.560 ;
      RECT 0.140 2515.520 16.100 2515.800 ;
      RECT 0.140 2517.760 16.100 2518.040 ;
      RECT 0.140 2520.000 16.100 2520.280 ;
      RECT 0.140 2522.240 16.100 2522.520 ;
      RECT 0.140 2524.480 16.100 2524.760 ;
      RECT 0.140 2526.720 16.100 2527.000 ;
      RECT 0.140 2528.960 16.100 2529.240 ;
      RECT 0.140 2531.200 16.100 2531.480 ;
      RECT 0.140 2533.440 16.100 2533.720 ;
      RECT 0.140 2535.680 16.100 2535.960 ;
      RECT 0.140 2537.920 16.100 2538.200 ;
      RECT 0.140 2540.160 16.100 2540.440 ;
      RECT 0.140 2542.400 16.100 2542.680 ;
      RECT 0.140 2544.640 16.100 2544.920 ;
      RECT 0.140 2546.880 16.100 2547.160 ;
      RECT 0.140 2549.120 16.100 2549.400 ;
      RECT 0.140 2551.360 16.100 2551.640 ;
      RECT 0.140 2553.600 16.100 2553.880 ;
      RECT 0.140 2555.840 16.100 2556.120 ;
      RECT 0.140 2558.080 16.100 2558.360 ;
      RECT 0.140 2560.320 16.100 2560.600 ;
      RECT 0.140 2562.560 16.100 2562.840 ;
      RECT 0.140 2564.800 16.100 2565.080 ;
      RECT 0.140 2567.040 16.100 2567.320 ;
      RECT 0.140 2569.280 16.100 2569.560 ;
      RECT 0.140 2571.520 16.100 2571.800 ;
      RECT 0.140 2573.760 16.100 2574.040 ;
      RECT 0.140 2576.000 16.100 2576.280 ;
      RECT 0.140 2578.240 16.100 2578.520 ;
      RECT 0.140 2580.480 16.100 2580.760 ;
    END
  END VSS
  PIN VDD
    DIRECTION INOUT ;
    USE POWER ;
    PORT
      LAYER metal3 ;
      RECT 0.140 1.120 16.100 1.400 ;
      RECT 0.140 3.360 16.100 3.640 ;
      RECT 0.140 5.600 16.100 5.880 ;
      RECT 0.140 7.840 16.100 8.120 ;
      RECT 0.140 10.080 16.100 10.360 ;
      RECT 0.140 12.320 16.100 12.600 ;
      RECT 0.140 14.560 16.100 14.840 ;
      RECT 0.140 16.800 16.100 17.080 ;
      RECT 0.140 19.040 16.100 19.320 ;
      RECT 0.140 21.280 16.100 21.560 ;
      RECT 0.140 23.520 16.100 23.800 ;
      RECT 0.140 25.760 16.100 26.040 ;
      RECT 0.140 28.000 16.100 28.280 ;
      RECT 0.140 30.240 16.100 30.520 ;
      RECT 0.140 32.480 16.100 32.760 ;
      RECT 0.140 34.720 16.100 35.000 ;
      RECT 0.140 36.960 16.100 37.240 ;
      RECT 0.140 39.200 16.100 39.480 ;
      RECT 0.140 41.440 16.100 41.720 ;
      RECT 0.140 43.680 16.100 43.960 ;
      RECT 0.140 45.920 16.100 46.200 ;
      RECT 0.140 48.160 16.100 48.440 ;
      RECT 0.140 50.400 16.100 50.680 ;
      RECT 0.140 52.640 16.100 52.920 ;
      RECT 0.140 54.880 16.100 55.160 ;
      RECT 0.140 57.120 16.100 57.400 ;
      RECT 0.140 59.360 16.100 59.640 ;
      RECT 0.140 61.600 16.100 61.880 ;
      RECT 0.140 63.840 16.100 64.120 ;
      RECT 0.140 66.080 16.100 66.360 ;
      RECT 0.140 68.320 16.100 68.600 ;
      RECT 0.140 70.560 16.100 70.840 ;
      RECT 0.140 72.800 16.100 73.080 ;
      RECT 0.140 75.040 16.100 75.320 ;
      RECT 0.140 77.280 16.100 77.560 ;
      RECT 0.140 79.520 16.100 79.800 ;
      RECT 0.140 81.760 16.100 82.040 ;
      RECT 0.140 84.000 16.100 84.280 ;
      RECT 0.140 86.240 16.100 86.520 ;
      RECT 0.140 88.480 16.100 88.760 ;
      RECT 0.140 90.720 16.100 91.000 ;
      RECT 0.140 92.960 16.100 93.240 ;
      RECT 0.140 95.200 16.100 95.480 ;
      RECT 0.140 97.440 16.100 97.720 ;
      RECT 0.140 99.680 16.100 99.960 ;
      RECT 0.140 101.920 16.100 102.200 ;
      RECT 0.140 104.160 16.100 104.440 ;
      RECT 0.140 106.400 16.100 106.680 ;
      RECT 0.140 108.640 16.100 108.920 ;
      RECT 0.140 110.880 16.100 111.160 ;
      RECT 0.140 113.120 16.100 113.400 ;
      RECT 0.140 115.360 16.100 115.640 ;
      RECT 0.140 117.600 16.100 117.880 ;
      RECT 0.140 119.840 16.100 120.120 ;
      RECT 0.140 122.080 16.100 122.360 ;
      RECT 0.140 124.320 16.100 124.600 ;
      RECT 0.140 126.560 16.100 126.840 ;
      RECT 0.140 128.800 16.100 129.080 ;
      RECT 0.140 131.040 16.100 131.320 ;
      RECT 0.140 133.280 16.100 133.560 ;
      RECT 0.140 135.520 16.100 135.800 ;
      RECT 0.140 137.760 16.100 138.040 ;
      RECT 0.140 140.000 16.100 140.280 ;
      RECT 0.140 142.240 16.100 142.520 ;
      RECT 0.140 144.480 16.100 144.760 ;
      RECT 0.140 146.720 16.100 147.000 ;
      RECT 0.140 148.960 16.100 149.240 ;
      RECT 0.140 151.200 16.100 151.480 ;
      RECT 0.140 153.440 16.100 153.720 ;
      RECT 0.140 155.680 16.100 155.960 ;
      RECT 0.140 157.920 16.100 158.200 ;
      RECT 0.140 160.160 16.100 160.440 ;
      RECT 0.140 162.400 16.100 162.680 ;
      RECT 0.140 164.640 16.100 164.920 ;
      RECT 0.140 166.880 16.100 167.160 ;
      RECT 0.140 169.120 16.100 169.400 ;
      RECT 0.140 171.360 16.100 171.640 ;
      RECT 0.140 173.600 16.100 173.880 ;
      RECT 0.140 175.840 16.100 176.120 ;
      RECT 0.140 178.080 16.100 178.360 ;
      RECT 0.140 180.320 16.100 180.600 ;
      RECT 0.140 182.560 16.100 182.840 ;
      RECT 0.140 184.800 16.100 185.080 ;
      RECT 0.140 187.040 16.100 187.320 ;
      RECT 0.140 189.280 16.100 189.560 ;
      RECT 0.140 191.520 16.100 191.800 ;
      RECT 0.140 193.760 16.100 194.040 ;
      RECT 0.140 196.000 16.100 196.280 ;
      RECT 0.140 198.240 16.100 198.520 ;
      RECT 0.140 200.480 16.100 200.760 ;
      RECT 0.140 202.720 16.100 203.000 ;
      RECT 0.140 204.960 16.100 205.240 ;
      RECT 0.140 207.200 16.100 207.480 ;
      RECT 0.140 209.440 16.100 209.720 ;
      RECT 0.140 211.680 16.100 211.960 ;
      RECT 0.140 213.920 16.100 214.200 ;
      RECT 0.140 216.160 16.100 216.440 ;
      RECT 0.140 218.400 16.100 218.680 ;
      RECT 0.140 220.640 16.100 220.920 ;
      RECT 0.140 222.880 16.100 223.160 ;
      RECT 0.140 225.120 16.100 225.400 ;
      RECT 0.140 227.360 16.100 227.640 ;
      RECT 0.140 229.600 16.100 229.880 ;
      RECT 0.140 231.840 16.100 232.120 ;
      RECT 0.140 234.080 16.100 234.360 ;
      RECT 0.140 236.320 16.100 236.600 ;
      RECT 0.140 238.560 16.100 238.840 ;
      RECT 0.140 240.800 16.100 241.080 ;
      RECT 0.140 243.040 16.100 243.320 ;
      RECT 0.140 245.280 16.100 245.560 ;
      RECT 0.140 247.520 16.100 247.800 ;
      RECT 0.140 249.760 16.100 250.040 ;
      RECT 0.140 252.000 16.100 252.280 ;
      RECT 0.140 254.240 16.100 254.520 ;
      RECT 0.140 256.480 16.100 256.760 ;
      RECT 0.140 258.720 16.100 259.000 ;
      RECT 0.140 260.960 16.100 261.240 ;
      RECT 0.140 263.200 16.100 263.480 ;
      RECT 0.140 265.440 16.100 265.720 ;
      RECT 0.140 267.680 16.100 267.960 ;
      RECT 0.140 269.920 16.100 270.200 ;
      RECT 0.140 272.160 16.100 272.440 ;
      RECT 0.140 274.400 16.100 274.680 ;
      RECT 0.140 276.640 16.100 276.920 ;
      RECT 0.140 278.880 16.100 279.160 ;
      RECT 0.140 281.120 16.100 281.400 ;
      RECT 0.140 283.360 16.100 283.640 ;
      RECT 0.140 285.600 16.100 285.880 ;
      RECT 0.140 287.840 16.100 288.120 ;
      RECT 0.140 290.080 16.100 290.360 ;
      RECT 0.140 292.320 16.100 292.600 ;
      RECT 0.140 294.560 16.100 294.840 ;
      RECT 0.140 296.800 16.100 297.080 ;
      RECT 0.140 299.040 16.100 299.320 ;
      RECT 0.140 301.280 16.100 301.560 ;
      RECT 0.140 303.520 16.100 303.800 ;
      RECT 0.140 305.760 16.100 306.040 ;
      RECT 0.140 308.000 16.100 308.280 ;
      RECT 0.140 310.240 16.100 310.520 ;
      RECT 0.140 312.480 16.100 312.760 ;
      RECT 0.140 314.720 16.100 315.000 ;
      RECT 0.140 316.960 16.100 317.240 ;
      RECT 0.140 319.200 16.100 319.480 ;
      RECT 0.140 321.440 16.100 321.720 ;
      RECT 0.140 323.680 16.100 323.960 ;
      RECT 0.140 325.920 16.100 326.200 ;
      RECT 0.140 328.160 16.100 328.440 ;
      RECT 0.140 330.400 16.100 330.680 ;
      RECT 0.140 332.640 16.100 332.920 ;
      RECT 0.140 334.880 16.100 335.160 ;
      RECT 0.140 337.120 16.100 337.400 ;
      RECT 0.140 339.360 16.100 339.640 ;
      RECT 0.140 341.600 16.100 341.880 ;
      RECT 0.140 343.840 16.100 344.120 ;
      RECT 0.140 346.080 16.100 346.360 ;
      RECT 0.140 348.320 16.100 348.600 ;
      RECT 0.140 350.560 16.100 350.840 ;
      RECT 0.140 352.800 16.100 353.080 ;
      RECT 0.140 355.040 16.100 355.320 ;
      RECT 0.140 357.280 16.100 357.560 ;
      RECT 0.140 359.520 16.100 359.800 ;
      RECT 0.140 361.760 16.100 362.040 ;
      RECT 0.140 364.000 16.100 364.280 ;
      RECT 0.140 366.240 16.100 366.520 ;
      RECT 0.140 368.480 16.100 368.760 ;
      RECT 0.140 370.720 16.100 371.000 ;
      RECT 0.140 372.960 16.100 373.240 ;
      RECT 0.140 375.200 16.100 375.480 ;
      RECT 0.140 377.440 16.100 377.720 ;
      RECT 0.140 379.680 16.100 379.960 ;
      RECT 0.140 381.920 16.100 382.200 ;
      RECT 0.140 384.160 16.100 384.440 ;
      RECT 0.140 386.400 16.100 386.680 ;
      RECT 0.140 388.640 16.100 388.920 ;
      RECT 0.140 390.880 16.100 391.160 ;
      RECT 0.140 393.120 16.100 393.400 ;
      RECT 0.140 395.360 16.100 395.640 ;
      RECT 0.140 397.600 16.100 397.880 ;
      RECT 0.140 399.840 16.100 400.120 ;
      RECT 0.140 402.080 16.100 402.360 ;
      RECT 0.140 404.320 16.100 404.600 ;
      RECT 0.140 406.560 16.100 406.840 ;
      RECT 0.140 408.800 16.100 409.080 ;
      RECT 0.140 411.040 16.100 411.320 ;
      RECT 0.140 413.280 16.100 413.560 ;
      RECT 0.140 415.520 16.100 415.800 ;
      RECT 0.140 417.760 16.100 418.040 ;
      RECT 0.140 420.000 16.100 420.280 ;
      RECT 0.140 422.240 16.100 422.520 ;
      RECT 0.140 424.480 16.100 424.760 ;
      RECT 0.140 426.720 16.100 427.000 ;
      RECT 0.140 428.960 16.100 429.240 ;
      RECT 0.140 431.200 16.100 431.480 ;
      RECT 0.140 433.440 16.100 433.720 ;
      RECT 0.140 435.680 16.100 435.960 ;
      RECT 0.140 437.920 16.100 438.200 ;
      RECT 0.140 440.160 16.100 440.440 ;
      RECT 0.140 442.400 16.100 442.680 ;
      RECT 0.140 444.640 16.100 444.920 ;
      RECT 0.140 446.880 16.100 447.160 ;
      RECT 0.140 449.120 16.100 449.400 ;
      RECT 0.140 451.360 16.100 451.640 ;
      RECT 0.140 453.600 16.100 453.880 ;
      RECT 0.140 455.840 16.100 456.120 ;
      RECT 0.140 458.080 16.100 458.360 ;
      RECT 0.140 460.320 16.100 460.600 ;
      RECT 0.140 462.560 16.100 462.840 ;
      RECT 0.140 464.800 16.100 465.080 ;
      RECT 0.140 467.040 16.100 467.320 ;
      RECT 0.140 469.280 16.100 469.560 ;
      RECT 0.140 471.520 16.100 471.800 ;
      RECT 0.140 473.760 16.100 474.040 ;
      RECT 0.140 476.000 16.100 476.280 ;
      RECT 0.140 478.240 16.100 478.520 ;
      RECT 0.140 480.480 16.100 480.760 ;
      RECT 0.140 482.720 16.100 483.000 ;
      RECT 0.140 484.960 16.100 485.240 ;
      RECT 0.140 487.200 16.100 487.480 ;
      RECT 0.140 489.440 16.100 489.720 ;
      RECT 0.140 491.680 16.100 491.960 ;
      RECT 0.140 493.920 16.100 494.200 ;
      RECT 0.140 496.160 16.100 496.440 ;
      RECT 0.140 498.400 16.100 498.680 ;
      RECT 0.140 500.640 16.100 500.920 ;
      RECT 0.140 502.880 16.100 503.160 ;
      RECT 0.140 505.120 16.100 505.400 ;
      RECT 0.140 507.360 16.100 507.640 ;
      RECT 0.140 509.600 16.100 509.880 ;
      RECT 0.140 511.840 16.100 512.120 ;
      RECT 0.140 514.080 16.100 514.360 ;
      RECT 0.140 516.320 16.100 516.600 ;
      RECT 0.140 518.560 16.100 518.840 ;
      RECT 0.140 520.800 16.100 521.080 ;
      RECT 0.140 523.040 16.100 523.320 ;
      RECT 0.140 525.280 16.100 525.560 ;
      RECT 0.140 527.520 16.100 527.800 ;
      RECT 0.140 529.760 16.100 530.040 ;
      RECT 0.140 532.000 16.100 532.280 ;
      RECT 0.140 534.240 16.100 534.520 ;
      RECT 0.140 536.480 16.100 536.760 ;
      RECT 0.140 538.720 16.100 539.000 ;
      RECT 0.140 540.960 16.100 541.240 ;
      RECT 0.140 543.200 16.100 543.480 ;
      RECT 0.140 545.440 16.100 545.720 ;
      RECT 0.140 547.680 16.100 547.960 ;
      RECT 0.140 549.920 16.100 550.200 ;
      RECT 0.140 552.160 16.100 552.440 ;
      RECT 0.140 554.400 16.100 554.680 ;
      RECT 0.140 556.640 16.100 556.920 ;
      RECT 0.140 558.880 16.100 559.160 ;
      RECT 0.140 561.120 16.100 561.400 ;
      RECT 0.140 563.360 16.100 563.640 ;
      RECT 0.140 565.600 16.100 565.880 ;
      RECT 0.140 567.840 16.100 568.120 ;
      RECT 0.140 570.080 16.100 570.360 ;
      RECT 0.140 572.320 16.100 572.600 ;
      RECT 0.140 574.560 16.100 574.840 ;
      RECT 0.140 576.800 16.100 577.080 ;
      RECT 0.140 579.040 16.100 579.320 ;
      RECT 0.140 581.280 16.100 581.560 ;
      RECT 0.140 583.520 16.100 583.800 ;
      RECT 0.140 585.760 16.100 586.040 ;
      RECT 0.140 588.000 16.100 588.280 ;
      RECT 0.140 590.240 16.100 590.520 ;
      RECT 0.140 592.480 16.100 592.760 ;
      RECT 0.140 594.720 16.100 595.000 ;
      RECT 0.140 596.960 16.100 597.240 ;
      RECT 0.140 599.200 16.100 599.480 ;
      RECT 0.140 601.440 16.100 601.720 ;
      RECT 0.140 603.680 16.100 603.960 ;
      RECT 0.140 605.920 16.100 606.200 ;
      RECT 0.140 608.160 16.100 608.440 ;
      RECT 0.140 610.400 16.100 610.680 ;
      RECT 0.140 612.640 16.100 612.920 ;
      RECT 0.140 614.880 16.100 615.160 ;
      RECT 0.140 617.120 16.100 617.400 ;
      RECT 0.140 619.360 16.100 619.640 ;
      RECT 0.140 621.600 16.100 621.880 ;
      RECT 0.140 623.840 16.100 624.120 ;
      RECT 0.140 626.080 16.100 626.360 ;
      RECT 0.140 628.320 16.100 628.600 ;
      RECT 0.140 630.560 16.100 630.840 ;
      RECT 0.140 632.800 16.100 633.080 ;
      RECT 0.140 635.040 16.100 635.320 ;
      RECT 0.140 637.280 16.100 637.560 ;
      RECT 0.140 639.520 16.100 639.800 ;
      RECT 0.140 641.760 16.100 642.040 ;
      RECT 0.140 644.000 16.100 644.280 ;
      RECT 0.140 646.240 16.100 646.520 ;
      RECT 0.140 648.480 16.100 648.760 ;
      RECT 0.140 650.720 16.100 651.000 ;
      RECT 0.140 652.960 16.100 653.240 ;
      RECT 0.140 655.200 16.100 655.480 ;
      RECT 0.140 657.440 16.100 657.720 ;
      RECT 0.140 659.680 16.100 659.960 ;
      RECT 0.140 661.920 16.100 662.200 ;
      RECT 0.140 664.160 16.100 664.440 ;
      RECT 0.140 666.400 16.100 666.680 ;
      RECT 0.140 668.640 16.100 668.920 ;
      RECT 0.140 670.880 16.100 671.160 ;
      RECT 0.140 673.120 16.100 673.400 ;
      RECT 0.140 675.360 16.100 675.640 ;
      RECT 0.140 677.600 16.100 677.880 ;
      RECT 0.140 679.840 16.100 680.120 ;
      RECT 0.140 682.080 16.100 682.360 ;
      RECT 0.140 684.320 16.100 684.600 ;
      RECT 0.140 686.560 16.100 686.840 ;
      RECT 0.140 688.800 16.100 689.080 ;
      RECT 0.140 691.040 16.100 691.320 ;
      RECT 0.140 693.280 16.100 693.560 ;
      RECT 0.140 695.520 16.100 695.800 ;
      RECT 0.140 697.760 16.100 698.040 ;
      RECT 0.140 700.000 16.100 700.280 ;
      RECT 0.140 702.240 16.100 702.520 ;
      RECT 0.140 704.480 16.100 704.760 ;
      RECT 0.140 706.720 16.100 707.000 ;
      RECT 0.140 708.960 16.100 709.240 ;
      RECT 0.140 711.200 16.100 711.480 ;
      RECT 0.140 713.440 16.100 713.720 ;
      RECT 0.140 715.680 16.100 715.960 ;
      RECT 0.140 717.920 16.100 718.200 ;
      RECT 0.140 720.160 16.100 720.440 ;
      RECT 0.140 722.400 16.100 722.680 ;
      RECT 0.140 724.640 16.100 724.920 ;
      RECT 0.140 726.880 16.100 727.160 ;
      RECT 0.140 729.120 16.100 729.400 ;
      RECT 0.140 731.360 16.100 731.640 ;
      RECT 0.140 733.600 16.100 733.880 ;
      RECT 0.140 735.840 16.100 736.120 ;
      RECT 0.140 738.080 16.100 738.360 ;
      RECT 0.140 740.320 16.100 740.600 ;
      RECT 0.140 742.560 16.100 742.840 ;
      RECT 0.140 744.800 16.100 745.080 ;
      RECT 0.140 747.040 16.100 747.320 ;
      RECT 0.140 749.280 16.100 749.560 ;
      RECT 0.140 751.520 16.100 751.800 ;
      RECT 0.140 753.760 16.100 754.040 ;
      RECT 0.140 756.000 16.100 756.280 ;
      RECT 0.140 758.240 16.100 758.520 ;
      RECT 0.140 760.480 16.100 760.760 ;
      RECT 0.140 762.720 16.100 763.000 ;
      RECT 0.140 764.960 16.100 765.240 ;
      RECT 0.140 767.200 16.100 767.480 ;
      RECT 0.140 769.440 16.100 769.720 ;
      RECT 0.140 771.680 16.100 771.960 ;
      RECT 0.140 773.920 16.100 774.200 ;
      RECT 0.140 776.160 16.100 776.440 ;
      RECT 0.140 778.400 16.100 778.680 ;
      RECT 0.140 780.640 16.100 780.920 ;
      RECT 0.140 782.880 16.100 783.160 ;
      RECT 0.140 785.120 16.100 785.400 ;
      RECT 0.140 787.360 16.100 787.640 ;
      RECT 0.140 789.600 16.100 789.880 ;
      RECT 0.140 791.840 16.100 792.120 ;
      RECT 0.140 794.080 16.100 794.360 ;
      RECT 0.140 796.320 16.100 796.600 ;
      RECT 0.140 798.560 16.100 798.840 ;
      RECT 0.140 800.800 16.100 801.080 ;
      RECT 0.140 803.040 16.100 803.320 ;
      RECT 0.140 805.280 16.100 805.560 ;
      RECT 0.140 807.520 16.100 807.800 ;
      RECT 0.140 809.760 16.100 810.040 ;
      RECT 0.140 812.000 16.100 812.280 ;
      RECT 0.140 814.240 16.100 814.520 ;
      RECT 0.140 816.480 16.100 816.760 ;
      RECT 0.140 818.720 16.100 819.000 ;
      RECT 0.140 820.960 16.100 821.240 ;
      RECT 0.140 823.200 16.100 823.480 ;
      RECT 0.140 825.440 16.100 825.720 ;
      RECT 0.140 827.680 16.100 827.960 ;
      RECT 0.140 829.920 16.100 830.200 ;
      RECT 0.140 832.160 16.100 832.440 ;
      RECT 0.140 834.400 16.100 834.680 ;
      RECT 0.140 836.640 16.100 836.920 ;
      RECT 0.140 838.880 16.100 839.160 ;
      RECT 0.140 841.120 16.100 841.400 ;
      RECT 0.140 843.360 16.100 843.640 ;
      RECT 0.140 845.600 16.100 845.880 ;
      RECT 0.140 847.840 16.100 848.120 ;
      RECT 0.140 850.080 16.100 850.360 ;
      RECT 0.140 852.320 16.100 852.600 ;
      RECT 0.140 854.560 16.100 854.840 ;
      RECT 0.140 856.800 16.100 857.080 ;
      RECT 0.140 859.040 16.100 859.320 ;
      RECT 0.140 861.280 16.100 861.560 ;
      RECT 0.140 863.520 16.100 863.800 ;
      RECT 0.140 865.760 16.100 866.040 ;
      RECT 0.140 868.000 16.100 868.280 ;
      RECT 0.140 870.240 16.100 870.520 ;
      RECT 0.140 872.480 16.100 872.760 ;
      RECT 0.140 874.720 16.100 875.000 ;
      RECT 0.140 876.960 16.100 877.240 ;
      RECT 0.140 879.200 16.100 879.480 ;
      RECT 0.140 881.440 16.100 881.720 ;
      RECT 0.140 883.680 16.100 883.960 ;
      RECT 0.140 885.920 16.100 886.200 ;
      RECT 0.140 888.160 16.100 888.440 ;
      RECT 0.140 890.400 16.100 890.680 ;
      RECT 0.140 892.640 16.100 892.920 ;
      RECT 0.140 894.880 16.100 895.160 ;
      RECT 0.140 897.120 16.100 897.400 ;
      RECT 0.140 899.360 16.100 899.640 ;
      RECT 0.140 901.600 16.100 901.880 ;
      RECT 0.140 903.840 16.100 904.120 ;
      RECT 0.140 906.080 16.100 906.360 ;
      RECT 0.140 908.320 16.100 908.600 ;
      RECT 0.140 910.560 16.100 910.840 ;
      RECT 0.140 912.800 16.100 913.080 ;
      RECT 0.140 915.040 16.100 915.320 ;
      RECT 0.140 917.280 16.100 917.560 ;
      RECT 0.140 919.520 16.100 919.800 ;
      RECT 0.140 921.760 16.100 922.040 ;
      RECT 0.140 924.000 16.100 924.280 ;
      RECT 0.140 926.240 16.100 926.520 ;
      RECT 0.140 928.480 16.100 928.760 ;
      RECT 0.140 930.720 16.100 931.000 ;
      RECT 0.140 932.960 16.100 933.240 ;
      RECT 0.140 935.200 16.100 935.480 ;
      RECT 0.140 937.440 16.100 937.720 ;
      RECT 0.140 939.680 16.100 939.960 ;
      RECT 0.140 941.920 16.100 942.200 ;
      RECT 0.140 944.160 16.100 944.440 ;
      RECT 0.140 946.400 16.100 946.680 ;
      RECT 0.140 948.640 16.100 948.920 ;
      RECT 0.140 950.880 16.100 951.160 ;
      RECT 0.140 953.120 16.100 953.400 ;
      RECT 0.140 955.360 16.100 955.640 ;
      RECT 0.140 957.600 16.100 957.880 ;
      RECT 0.140 959.840 16.100 960.120 ;
      RECT 0.140 962.080 16.100 962.360 ;
      RECT 0.140 964.320 16.100 964.600 ;
      RECT 0.140 966.560 16.100 966.840 ;
      RECT 0.140 968.800 16.100 969.080 ;
      RECT 0.140 971.040 16.100 971.320 ;
      RECT 0.140 973.280 16.100 973.560 ;
      RECT 0.140 975.520 16.100 975.800 ;
      RECT 0.140 977.760 16.100 978.040 ;
      RECT 0.140 980.000 16.100 980.280 ;
      RECT 0.140 982.240 16.100 982.520 ;
      RECT 0.140 984.480 16.100 984.760 ;
      RECT 0.140 986.720 16.100 987.000 ;
      RECT 0.140 988.960 16.100 989.240 ;
      RECT 0.140 991.200 16.100 991.480 ;
      RECT 0.140 993.440 16.100 993.720 ;
      RECT 0.140 995.680 16.100 995.960 ;
      RECT 0.140 997.920 16.100 998.200 ;
      RECT 0.140 1000.160 16.100 1000.440 ;
      RECT 0.140 1002.400 16.100 1002.680 ;
      RECT 0.140 1004.640 16.100 1004.920 ;
      RECT 0.140 1006.880 16.100 1007.160 ;
      RECT 0.140 1009.120 16.100 1009.400 ;
      RECT 0.140 1011.360 16.100 1011.640 ;
      RECT 0.140 1013.600 16.100 1013.880 ;
      RECT 0.140 1015.840 16.100 1016.120 ;
      RECT 0.140 1018.080 16.100 1018.360 ;
      RECT 0.140 1020.320 16.100 1020.600 ;
      RECT 0.140 1022.560 16.100 1022.840 ;
      RECT 0.140 1024.800 16.100 1025.080 ;
      RECT 0.140 1027.040 16.100 1027.320 ;
      RECT 0.140 1029.280 16.100 1029.560 ;
      RECT 0.140 1031.520 16.100 1031.800 ;
      RECT 0.140 1033.760 16.100 1034.040 ;
      RECT 0.140 1036.000 16.100 1036.280 ;
      RECT 0.140 1038.240 16.100 1038.520 ;
      RECT 0.140 1040.480 16.100 1040.760 ;
      RECT 0.140 1042.720 16.100 1043.000 ;
      RECT 0.140 1044.960 16.100 1045.240 ;
      RECT 0.140 1047.200 16.100 1047.480 ;
      RECT 0.140 1049.440 16.100 1049.720 ;
      RECT 0.140 1051.680 16.100 1051.960 ;
      RECT 0.140 1053.920 16.100 1054.200 ;
      RECT 0.140 1056.160 16.100 1056.440 ;
      RECT 0.140 1058.400 16.100 1058.680 ;
      RECT 0.140 1060.640 16.100 1060.920 ;
      RECT 0.140 1062.880 16.100 1063.160 ;
      RECT 0.140 1065.120 16.100 1065.400 ;
      RECT 0.140 1067.360 16.100 1067.640 ;
      RECT 0.140 1069.600 16.100 1069.880 ;
      RECT 0.140 1071.840 16.100 1072.120 ;
      RECT 0.140 1074.080 16.100 1074.360 ;
      RECT 0.140 1076.320 16.100 1076.600 ;
      RECT 0.140 1078.560 16.100 1078.840 ;
      RECT 0.140 1080.800 16.100 1081.080 ;
      RECT 0.140 1083.040 16.100 1083.320 ;
      RECT 0.140 1085.280 16.100 1085.560 ;
      RECT 0.140 1087.520 16.100 1087.800 ;
      RECT 0.140 1089.760 16.100 1090.040 ;
      RECT 0.140 1092.000 16.100 1092.280 ;
      RECT 0.140 1094.240 16.100 1094.520 ;
      RECT 0.140 1096.480 16.100 1096.760 ;
      RECT 0.140 1098.720 16.100 1099.000 ;
      RECT 0.140 1100.960 16.100 1101.240 ;
      RECT 0.140 1103.200 16.100 1103.480 ;
      RECT 0.140 1105.440 16.100 1105.720 ;
      RECT 0.140 1107.680 16.100 1107.960 ;
      RECT 0.140 1109.920 16.100 1110.200 ;
      RECT 0.140 1112.160 16.100 1112.440 ;
      RECT 0.140 1114.400 16.100 1114.680 ;
      RECT 0.140 1116.640 16.100 1116.920 ;
      RECT 0.140 1118.880 16.100 1119.160 ;
      RECT 0.140 1121.120 16.100 1121.400 ;
      RECT 0.140 1123.360 16.100 1123.640 ;
      RECT 0.140 1125.600 16.100 1125.880 ;
      RECT 0.140 1127.840 16.100 1128.120 ;
      RECT 0.140 1130.080 16.100 1130.360 ;
      RECT 0.140 1132.320 16.100 1132.600 ;
      RECT 0.140 1134.560 16.100 1134.840 ;
      RECT 0.140 1136.800 16.100 1137.080 ;
      RECT 0.140 1139.040 16.100 1139.320 ;
      RECT 0.140 1141.280 16.100 1141.560 ;
      RECT 0.140 1143.520 16.100 1143.800 ;
      RECT 0.140 1145.760 16.100 1146.040 ;
      RECT 0.140 1148.000 16.100 1148.280 ;
      RECT 0.140 1150.240 16.100 1150.520 ;
      RECT 0.140 1152.480 16.100 1152.760 ;
      RECT 0.140 1154.720 16.100 1155.000 ;
      RECT 0.140 1156.960 16.100 1157.240 ;
      RECT 0.140 1159.200 16.100 1159.480 ;
      RECT 0.140 1161.440 16.100 1161.720 ;
      RECT 0.140 1163.680 16.100 1163.960 ;
      RECT 0.140 1165.920 16.100 1166.200 ;
      RECT 0.140 1168.160 16.100 1168.440 ;
      RECT 0.140 1170.400 16.100 1170.680 ;
      RECT 0.140 1172.640 16.100 1172.920 ;
      RECT 0.140 1174.880 16.100 1175.160 ;
      RECT 0.140 1177.120 16.100 1177.400 ;
      RECT 0.140 1179.360 16.100 1179.640 ;
      RECT 0.140 1181.600 16.100 1181.880 ;
      RECT 0.140 1183.840 16.100 1184.120 ;
      RECT 0.140 1186.080 16.100 1186.360 ;
      RECT 0.140 1188.320 16.100 1188.600 ;
      RECT 0.140 1190.560 16.100 1190.840 ;
      RECT 0.140 1192.800 16.100 1193.080 ;
      RECT 0.140 1195.040 16.100 1195.320 ;
      RECT 0.140 1197.280 16.100 1197.560 ;
      RECT 0.140 1199.520 16.100 1199.800 ;
      RECT 0.140 1201.760 16.100 1202.040 ;
      RECT 0.140 1204.000 16.100 1204.280 ;
      RECT 0.140 1206.240 16.100 1206.520 ;
      RECT 0.140 1208.480 16.100 1208.760 ;
      RECT 0.140 1210.720 16.100 1211.000 ;
      RECT 0.140 1212.960 16.100 1213.240 ;
      RECT 0.140 1215.200 16.100 1215.480 ;
      RECT 0.140 1217.440 16.100 1217.720 ;
      RECT 0.140 1219.680 16.100 1219.960 ;
      RECT 0.140 1221.920 16.100 1222.200 ;
      RECT 0.140 1224.160 16.100 1224.440 ;
      RECT 0.140 1226.400 16.100 1226.680 ;
      RECT 0.140 1228.640 16.100 1228.920 ;
      RECT 0.140 1230.880 16.100 1231.160 ;
      RECT 0.140 1233.120 16.100 1233.400 ;
      RECT 0.140 1235.360 16.100 1235.640 ;
      RECT 0.140 1237.600 16.100 1237.880 ;
      RECT 0.140 1239.840 16.100 1240.120 ;
      RECT 0.140 1242.080 16.100 1242.360 ;
      RECT 0.140 1244.320 16.100 1244.600 ;
      RECT 0.140 1246.560 16.100 1246.840 ;
      RECT 0.140 1248.800 16.100 1249.080 ;
      RECT 0.140 1251.040 16.100 1251.320 ;
      RECT 0.140 1253.280 16.100 1253.560 ;
      RECT 0.140 1255.520 16.100 1255.800 ;
      RECT 0.140 1257.760 16.100 1258.040 ;
      RECT 0.140 1260.000 16.100 1260.280 ;
      RECT 0.140 1262.240 16.100 1262.520 ;
      RECT 0.140 1264.480 16.100 1264.760 ;
      RECT 0.140 1266.720 16.100 1267.000 ;
      RECT 0.140 1268.960 16.100 1269.240 ;
      RECT 0.140 1271.200 16.100 1271.480 ;
      RECT 0.140 1273.440 16.100 1273.720 ;
      RECT 0.140 1275.680 16.100 1275.960 ;
      RECT 0.140 1277.920 16.100 1278.200 ;
      RECT 0.140 1280.160 16.100 1280.440 ;
      RECT 0.140 1282.400 16.100 1282.680 ;
      RECT 0.140 1284.640 16.100 1284.920 ;
      RECT 0.140 1286.880 16.100 1287.160 ;
      RECT 0.140 1289.120 16.100 1289.400 ;
      RECT 0.140 1291.360 16.100 1291.640 ;
      RECT 0.140 1293.600 16.100 1293.880 ;
      RECT 0.140 1295.840 16.100 1296.120 ;
      RECT 0.140 1298.080 16.100 1298.360 ;
      RECT 0.140 1300.320 16.100 1300.600 ;
      RECT 0.140 1302.560 16.100 1302.840 ;
      RECT 0.140 1304.800 16.100 1305.080 ;
      RECT 0.140 1307.040 16.100 1307.320 ;
      RECT 0.140 1309.280 16.100 1309.560 ;
      RECT 0.140 1311.520 16.100 1311.800 ;
      RECT 0.140 1313.760 16.100 1314.040 ;
      RECT 0.140 1316.000 16.100 1316.280 ;
      RECT 0.140 1318.240 16.100 1318.520 ;
      RECT 0.140 1320.480 16.100 1320.760 ;
      RECT 0.140 1322.720 16.100 1323.000 ;
      RECT 0.140 1324.960 16.100 1325.240 ;
      RECT 0.140 1327.200 16.100 1327.480 ;
      RECT 0.140 1329.440 16.100 1329.720 ;
      RECT 0.140 1331.680 16.100 1331.960 ;
      RECT 0.140 1333.920 16.100 1334.200 ;
      RECT 0.140 1336.160 16.100 1336.440 ;
      RECT 0.140 1338.400 16.100 1338.680 ;
      RECT 0.140 1340.640 16.100 1340.920 ;
      RECT 0.140 1342.880 16.100 1343.160 ;
      RECT 0.140 1345.120 16.100 1345.400 ;
      RECT 0.140 1347.360 16.100 1347.640 ;
      RECT 0.140 1349.600 16.100 1349.880 ;
      RECT 0.140 1351.840 16.100 1352.120 ;
      RECT 0.140 1354.080 16.100 1354.360 ;
      RECT 0.140 1356.320 16.100 1356.600 ;
      RECT 0.140 1358.560 16.100 1358.840 ;
      RECT 0.140 1360.800 16.100 1361.080 ;
      RECT 0.140 1363.040 16.100 1363.320 ;
      RECT 0.140 1365.280 16.100 1365.560 ;
      RECT 0.140 1367.520 16.100 1367.800 ;
      RECT 0.140 1369.760 16.100 1370.040 ;
      RECT 0.140 1372.000 16.100 1372.280 ;
      RECT 0.140 1374.240 16.100 1374.520 ;
      RECT 0.140 1376.480 16.100 1376.760 ;
      RECT 0.140 1378.720 16.100 1379.000 ;
      RECT 0.140 1380.960 16.100 1381.240 ;
      RECT 0.140 1383.200 16.100 1383.480 ;
      RECT 0.140 1385.440 16.100 1385.720 ;
      RECT 0.140 1387.680 16.100 1387.960 ;
      RECT 0.140 1389.920 16.100 1390.200 ;
      RECT 0.140 1392.160 16.100 1392.440 ;
      RECT 0.140 1394.400 16.100 1394.680 ;
      RECT 0.140 1396.640 16.100 1396.920 ;
      RECT 0.140 1398.880 16.100 1399.160 ;
      RECT 0.140 1401.120 16.100 1401.400 ;
      RECT 0.140 1403.360 16.100 1403.640 ;
      RECT 0.140 1405.600 16.100 1405.880 ;
      RECT 0.140 1407.840 16.100 1408.120 ;
      RECT 0.140 1410.080 16.100 1410.360 ;
      RECT 0.140 1412.320 16.100 1412.600 ;
      RECT 0.140 1414.560 16.100 1414.840 ;
      RECT 0.140 1416.800 16.100 1417.080 ;
      RECT 0.140 1419.040 16.100 1419.320 ;
      RECT 0.140 1421.280 16.100 1421.560 ;
      RECT 0.140 1423.520 16.100 1423.800 ;
      RECT 0.140 1425.760 16.100 1426.040 ;
      RECT 0.140 1428.000 16.100 1428.280 ;
      RECT 0.140 1430.240 16.100 1430.520 ;
      RECT 0.140 1432.480 16.100 1432.760 ;
      RECT 0.140 1434.720 16.100 1435.000 ;
      RECT 0.140 1436.960 16.100 1437.240 ;
      RECT 0.140 1439.200 16.100 1439.480 ;
      RECT 0.140 1441.440 16.100 1441.720 ;
      RECT 0.140 1443.680 16.100 1443.960 ;
      RECT 0.140 1445.920 16.100 1446.200 ;
      RECT 0.140 1448.160 16.100 1448.440 ;
      RECT 0.140 1450.400 16.100 1450.680 ;
      RECT 0.140 1452.640 16.100 1452.920 ;
      RECT 0.140 1454.880 16.100 1455.160 ;
      RECT 0.140 1457.120 16.100 1457.400 ;
      RECT 0.140 1459.360 16.100 1459.640 ;
      RECT 0.140 1461.600 16.100 1461.880 ;
      RECT 0.140 1463.840 16.100 1464.120 ;
      RECT 0.140 1466.080 16.100 1466.360 ;
      RECT 0.140 1468.320 16.100 1468.600 ;
      RECT 0.140 1470.560 16.100 1470.840 ;
      RECT 0.140 1472.800 16.100 1473.080 ;
      RECT 0.140 1475.040 16.100 1475.320 ;
      RECT 0.140 1477.280 16.100 1477.560 ;
      RECT 0.140 1479.520 16.100 1479.800 ;
      RECT 0.140 1481.760 16.100 1482.040 ;
      RECT 0.140 1484.000 16.100 1484.280 ;
      RECT 0.140 1486.240 16.100 1486.520 ;
      RECT 0.140 1488.480 16.100 1488.760 ;
      RECT 0.140 1490.720 16.100 1491.000 ;
      RECT 0.140 1492.960 16.100 1493.240 ;
      RECT 0.140 1495.200 16.100 1495.480 ;
      RECT 0.140 1497.440 16.100 1497.720 ;
      RECT 0.140 1499.680 16.100 1499.960 ;
      RECT 0.140 1501.920 16.100 1502.200 ;
      RECT 0.140 1504.160 16.100 1504.440 ;
      RECT 0.140 1506.400 16.100 1506.680 ;
      RECT 0.140 1508.640 16.100 1508.920 ;
      RECT 0.140 1510.880 16.100 1511.160 ;
      RECT 0.140 1513.120 16.100 1513.400 ;
      RECT 0.140 1515.360 16.100 1515.640 ;
      RECT 0.140 1517.600 16.100 1517.880 ;
      RECT 0.140 1519.840 16.100 1520.120 ;
      RECT 0.140 1522.080 16.100 1522.360 ;
      RECT 0.140 1524.320 16.100 1524.600 ;
      RECT 0.140 1526.560 16.100 1526.840 ;
      RECT 0.140 1528.800 16.100 1529.080 ;
      RECT 0.140 1531.040 16.100 1531.320 ;
      RECT 0.140 1533.280 16.100 1533.560 ;
      RECT 0.140 1535.520 16.100 1535.800 ;
      RECT 0.140 1537.760 16.100 1538.040 ;
      RECT 0.140 1540.000 16.100 1540.280 ;
      RECT 0.140 1542.240 16.100 1542.520 ;
      RECT 0.140 1544.480 16.100 1544.760 ;
      RECT 0.140 1546.720 16.100 1547.000 ;
      RECT 0.140 1548.960 16.100 1549.240 ;
      RECT 0.140 1551.200 16.100 1551.480 ;
      RECT 0.140 1553.440 16.100 1553.720 ;
      RECT 0.140 1555.680 16.100 1555.960 ;
      RECT 0.140 1557.920 16.100 1558.200 ;
      RECT 0.140 1560.160 16.100 1560.440 ;
      RECT 0.140 1562.400 16.100 1562.680 ;
      RECT 0.140 1564.640 16.100 1564.920 ;
      RECT 0.140 1566.880 16.100 1567.160 ;
      RECT 0.140 1569.120 16.100 1569.400 ;
      RECT 0.140 1571.360 16.100 1571.640 ;
      RECT 0.140 1573.600 16.100 1573.880 ;
      RECT 0.140 1575.840 16.100 1576.120 ;
      RECT 0.140 1578.080 16.100 1578.360 ;
      RECT 0.140 1580.320 16.100 1580.600 ;
      RECT 0.140 1582.560 16.100 1582.840 ;
      RECT 0.140 1584.800 16.100 1585.080 ;
      RECT 0.140 1587.040 16.100 1587.320 ;
      RECT 0.140 1589.280 16.100 1589.560 ;
      RECT 0.140 1591.520 16.100 1591.800 ;
      RECT 0.140 1593.760 16.100 1594.040 ;
      RECT 0.140 1596.000 16.100 1596.280 ;
      RECT 0.140 1598.240 16.100 1598.520 ;
      RECT 0.140 1600.480 16.100 1600.760 ;
      RECT 0.140 1602.720 16.100 1603.000 ;
      RECT 0.140 1604.960 16.100 1605.240 ;
      RECT 0.140 1607.200 16.100 1607.480 ;
      RECT 0.140 1609.440 16.100 1609.720 ;
      RECT 0.140 1611.680 16.100 1611.960 ;
      RECT 0.140 1613.920 16.100 1614.200 ;
      RECT 0.140 1616.160 16.100 1616.440 ;
      RECT 0.140 1618.400 16.100 1618.680 ;
      RECT 0.140 1620.640 16.100 1620.920 ;
      RECT 0.140 1622.880 16.100 1623.160 ;
      RECT 0.140 1625.120 16.100 1625.400 ;
      RECT 0.140 1627.360 16.100 1627.640 ;
      RECT 0.140 1629.600 16.100 1629.880 ;
      RECT 0.140 1631.840 16.100 1632.120 ;
      RECT 0.140 1634.080 16.100 1634.360 ;
      RECT 0.140 1636.320 16.100 1636.600 ;
      RECT 0.140 1638.560 16.100 1638.840 ;
      RECT 0.140 1640.800 16.100 1641.080 ;
      RECT 0.140 1643.040 16.100 1643.320 ;
      RECT 0.140 1645.280 16.100 1645.560 ;
      RECT 0.140 1647.520 16.100 1647.800 ;
      RECT 0.140 1649.760 16.100 1650.040 ;
      RECT 0.140 1652.000 16.100 1652.280 ;
      RECT 0.140 1654.240 16.100 1654.520 ;
      RECT 0.140 1656.480 16.100 1656.760 ;
      RECT 0.140 1658.720 16.100 1659.000 ;
      RECT 0.140 1660.960 16.100 1661.240 ;
      RECT 0.140 1663.200 16.100 1663.480 ;
      RECT 0.140 1665.440 16.100 1665.720 ;
      RECT 0.140 1667.680 16.100 1667.960 ;
      RECT 0.140 1669.920 16.100 1670.200 ;
      RECT 0.140 1672.160 16.100 1672.440 ;
      RECT 0.140 1674.400 16.100 1674.680 ;
      RECT 0.140 1676.640 16.100 1676.920 ;
      RECT 0.140 1678.880 16.100 1679.160 ;
      RECT 0.140 1681.120 16.100 1681.400 ;
      RECT 0.140 1683.360 16.100 1683.640 ;
      RECT 0.140 1685.600 16.100 1685.880 ;
      RECT 0.140 1687.840 16.100 1688.120 ;
      RECT 0.140 1690.080 16.100 1690.360 ;
      RECT 0.140 1692.320 16.100 1692.600 ;
      RECT 0.140 1694.560 16.100 1694.840 ;
      RECT 0.140 1696.800 16.100 1697.080 ;
      RECT 0.140 1699.040 16.100 1699.320 ;
      RECT 0.140 1701.280 16.100 1701.560 ;
      RECT 0.140 1703.520 16.100 1703.800 ;
      RECT 0.140 1705.760 16.100 1706.040 ;
      RECT 0.140 1708.000 16.100 1708.280 ;
      RECT 0.140 1710.240 16.100 1710.520 ;
      RECT 0.140 1712.480 16.100 1712.760 ;
      RECT 0.140 1714.720 16.100 1715.000 ;
      RECT 0.140 1716.960 16.100 1717.240 ;
      RECT 0.140 1719.200 16.100 1719.480 ;
      RECT 0.140 1721.440 16.100 1721.720 ;
      RECT 0.140 1723.680 16.100 1723.960 ;
      RECT 0.140 1725.920 16.100 1726.200 ;
      RECT 0.140 1728.160 16.100 1728.440 ;
      RECT 0.140 1730.400 16.100 1730.680 ;
      RECT 0.140 1732.640 16.100 1732.920 ;
      RECT 0.140 1734.880 16.100 1735.160 ;
      RECT 0.140 1737.120 16.100 1737.400 ;
      RECT 0.140 1739.360 16.100 1739.640 ;
      RECT 0.140 1741.600 16.100 1741.880 ;
      RECT 0.140 1743.840 16.100 1744.120 ;
      RECT 0.140 1746.080 16.100 1746.360 ;
      RECT 0.140 1748.320 16.100 1748.600 ;
      RECT 0.140 1750.560 16.100 1750.840 ;
      RECT 0.140 1752.800 16.100 1753.080 ;
      RECT 0.140 1755.040 16.100 1755.320 ;
      RECT 0.140 1757.280 16.100 1757.560 ;
      RECT 0.140 1759.520 16.100 1759.800 ;
      RECT 0.140 1761.760 16.100 1762.040 ;
      RECT 0.140 1764.000 16.100 1764.280 ;
      RECT 0.140 1766.240 16.100 1766.520 ;
      RECT 0.140 1768.480 16.100 1768.760 ;
      RECT 0.140 1770.720 16.100 1771.000 ;
      RECT 0.140 1772.960 16.100 1773.240 ;
      RECT 0.140 1775.200 16.100 1775.480 ;
      RECT 0.140 1777.440 16.100 1777.720 ;
      RECT 0.140 1779.680 16.100 1779.960 ;
      RECT 0.140 1781.920 16.100 1782.200 ;
      RECT 0.140 1784.160 16.100 1784.440 ;
      RECT 0.140 1786.400 16.100 1786.680 ;
      RECT 0.140 1788.640 16.100 1788.920 ;
      RECT 0.140 1790.880 16.100 1791.160 ;
      RECT 0.140 1793.120 16.100 1793.400 ;
      RECT 0.140 1795.360 16.100 1795.640 ;
      RECT 0.140 1797.600 16.100 1797.880 ;
      RECT 0.140 1799.840 16.100 1800.120 ;
      RECT 0.140 1802.080 16.100 1802.360 ;
      RECT 0.140 1804.320 16.100 1804.600 ;
      RECT 0.140 1806.560 16.100 1806.840 ;
      RECT 0.140 1808.800 16.100 1809.080 ;
      RECT 0.140 1811.040 16.100 1811.320 ;
      RECT 0.140 1813.280 16.100 1813.560 ;
      RECT 0.140 1815.520 16.100 1815.800 ;
      RECT 0.140 1817.760 16.100 1818.040 ;
      RECT 0.140 1820.000 16.100 1820.280 ;
      RECT 0.140 1822.240 16.100 1822.520 ;
      RECT 0.140 1824.480 16.100 1824.760 ;
      RECT 0.140 1826.720 16.100 1827.000 ;
      RECT 0.140 1828.960 16.100 1829.240 ;
      RECT 0.140 1831.200 16.100 1831.480 ;
      RECT 0.140 1833.440 16.100 1833.720 ;
      RECT 0.140 1835.680 16.100 1835.960 ;
      RECT 0.140 1837.920 16.100 1838.200 ;
      RECT 0.140 1840.160 16.100 1840.440 ;
      RECT 0.140 1842.400 16.100 1842.680 ;
      RECT 0.140 1844.640 16.100 1844.920 ;
      RECT 0.140 1846.880 16.100 1847.160 ;
      RECT 0.140 1849.120 16.100 1849.400 ;
      RECT 0.140 1851.360 16.100 1851.640 ;
      RECT 0.140 1853.600 16.100 1853.880 ;
      RECT 0.140 1855.840 16.100 1856.120 ;
      RECT 0.140 1858.080 16.100 1858.360 ;
      RECT 0.140 1860.320 16.100 1860.600 ;
      RECT 0.140 1862.560 16.100 1862.840 ;
      RECT 0.140 1864.800 16.100 1865.080 ;
      RECT 0.140 1867.040 16.100 1867.320 ;
      RECT 0.140 1869.280 16.100 1869.560 ;
      RECT 0.140 1871.520 16.100 1871.800 ;
      RECT 0.140 1873.760 16.100 1874.040 ;
      RECT 0.140 1876.000 16.100 1876.280 ;
      RECT 0.140 1878.240 16.100 1878.520 ;
      RECT 0.140 1880.480 16.100 1880.760 ;
      RECT 0.140 1882.720 16.100 1883.000 ;
      RECT 0.140 1884.960 16.100 1885.240 ;
      RECT 0.140 1887.200 16.100 1887.480 ;
      RECT 0.140 1889.440 16.100 1889.720 ;
      RECT 0.140 1891.680 16.100 1891.960 ;
      RECT 0.140 1893.920 16.100 1894.200 ;
      RECT 0.140 1896.160 16.100 1896.440 ;
      RECT 0.140 1898.400 16.100 1898.680 ;
      RECT 0.140 1900.640 16.100 1900.920 ;
      RECT 0.140 1902.880 16.100 1903.160 ;
      RECT 0.140 1905.120 16.100 1905.400 ;
      RECT 0.140 1907.360 16.100 1907.640 ;
      RECT 0.140 1909.600 16.100 1909.880 ;
      RECT 0.140 1911.840 16.100 1912.120 ;
      RECT 0.140 1914.080 16.100 1914.360 ;
      RECT 0.140 1916.320 16.100 1916.600 ;
      RECT 0.140 1918.560 16.100 1918.840 ;
      RECT 0.140 1920.800 16.100 1921.080 ;
      RECT 0.140 1923.040 16.100 1923.320 ;
      RECT 0.140 1925.280 16.100 1925.560 ;
      RECT 0.140 1927.520 16.100 1927.800 ;
      RECT 0.140 1929.760 16.100 1930.040 ;
      RECT 0.140 1932.000 16.100 1932.280 ;
      RECT 0.140 1934.240 16.100 1934.520 ;
      RECT 0.140 1936.480 16.100 1936.760 ;
      RECT 0.140 1938.720 16.100 1939.000 ;
      RECT 0.140 1940.960 16.100 1941.240 ;
      RECT 0.140 1943.200 16.100 1943.480 ;
      RECT 0.140 1945.440 16.100 1945.720 ;
      RECT 0.140 1947.680 16.100 1947.960 ;
      RECT 0.140 1949.920 16.100 1950.200 ;
      RECT 0.140 1952.160 16.100 1952.440 ;
      RECT 0.140 1954.400 16.100 1954.680 ;
      RECT 0.140 1956.640 16.100 1956.920 ;
      RECT 0.140 1958.880 16.100 1959.160 ;
      RECT 0.140 1961.120 16.100 1961.400 ;
      RECT 0.140 1963.360 16.100 1963.640 ;
      RECT 0.140 1965.600 16.100 1965.880 ;
      RECT 0.140 1967.840 16.100 1968.120 ;
      RECT 0.140 1970.080 16.100 1970.360 ;
      RECT 0.140 1972.320 16.100 1972.600 ;
      RECT 0.140 1974.560 16.100 1974.840 ;
      RECT 0.140 1976.800 16.100 1977.080 ;
      RECT 0.140 1979.040 16.100 1979.320 ;
      RECT 0.140 1981.280 16.100 1981.560 ;
      RECT 0.140 1983.520 16.100 1983.800 ;
      RECT 0.140 1985.760 16.100 1986.040 ;
      RECT 0.140 1988.000 16.100 1988.280 ;
      RECT 0.140 1990.240 16.100 1990.520 ;
      RECT 0.140 1992.480 16.100 1992.760 ;
      RECT 0.140 1994.720 16.100 1995.000 ;
      RECT 0.140 1996.960 16.100 1997.240 ;
      RECT 0.140 1999.200 16.100 1999.480 ;
      RECT 0.140 2001.440 16.100 2001.720 ;
      RECT 0.140 2003.680 16.100 2003.960 ;
      RECT 0.140 2005.920 16.100 2006.200 ;
      RECT 0.140 2008.160 16.100 2008.440 ;
      RECT 0.140 2010.400 16.100 2010.680 ;
      RECT 0.140 2012.640 16.100 2012.920 ;
      RECT 0.140 2014.880 16.100 2015.160 ;
      RECT 0.140 2017.120 16.100 2017.400 ;
      RECT 0.140 2019.360 16.100 2019.640 ;
      RECT 0.140 2021.600 16.100 2021.880 ;
      RECT 0.140 2023.840 16.100 2024.120 ;
      RECT 0.140 2026.080 16.100 2026.360 ;
      RECT 0.140 2028.320 16.100 2028.600 ;
      RECT 0.140 2030.560 16.100 2030.840 ;
      RECT 0.140 2032.800 16.100 2033.080 ;
      RECT 0.140 2035.040 16.100 2035.320 ;
      RECT 0.140 2037.280 16.100 2037.560 ;
      RECT 0.140 2039.520 16.100 2039.800 ;
      RECT 0.140 2041.760 16.100 2042.040 ;
      RECT 0.140 2044.000 16.100 2044.280 ;
      RECT 0.140 2046.240 16.100 2046.520 ;
      RECT 0.140 2048.480 16.100 2048.760 ;
      RECT 0.140 2050.720 16.100 2051.000 ;
      RECT 0.140 2052.960 16.100 2053.240 ;
      RECT 0.140 2055.200 16.100 2055.480 ;
      RECT 0.140 2057.440 16.100 2057.720 ;
      RECT 0.140 2059.680 16.100 2059.960 ;
      RECT 0.140 2061.920 16.100 2062.200 ;
      RECT 0.140 2064.160 16.100 2064.440 ;
      RECT 0.140 2066.400 16.100 2066.680 ;
      RECT 0.140 2068.640 16.100 2068.920 ;
      RECT 0.140 2070.880 16.100 2071.160 ;
      RECT 0.140 2073.120 16.100 2073.400 ;
      RECT 0.140 2075.360 16.100 2075.640 ;
      RECT 0.140 2077.600 16.100 2077.880 ;
      RECT 0.140 2079.840 16.100 2080.120 ;
      RECT 0.140 2082.080 16.100 2082.360 ;
      RECT 0.140 2084.320 16.100 2084.600 ;
      RECT 0.140 2086.560 16.100 2086.840 ;
      RECT 0.140 2088.800 16.100 2089.080 ;
      RECT 0.140 2091.040 16.100 2091.320 ;
      RECT 0.140 2093.280 16.100 2093.560 ;
      RECT 0.140 2095.520 16.100 2095.800 ;
      RECT 0.140 2097.760 16.100 2098.040 ;
      RECT 0.140 2100.000 16.100 2100.280 ;
      RECT 0.140 2102.240 16.100 2102.520 ;
      RECT 0.140 2104.480 16.100 2104.760 ;
      RECT 0.140 2106.720 16.100 2107.000 ;
      RECT 0.140 2108.960 16.100 2109.240 ;
      RECT 0.140 2111.200 16.100 2111.480 ;
      RECT 0.140 2113.440 16.100 2113.720 ;
      RECT 0.140 2115.680 16.100 2115.960 ;
      RECT 0.140 2117.920 16.100 2118.200 ;
      RECT 0.140 2120.160 16.100 2120.440 ;
      RECT 0.140 2122.400 16.100 2122.680 ;
      RECT 0.140 2124.640 16.100 2124.920 ;
      RECT 0.140 2126.880 16.100 2127.160 ;
      RECT 0.140 2129.120 16.100 2129.400 ;
      RECT 0.140 2131.360 16.100 2131.640 ;
      RECT 0.140 2133.600 16.100 2133.880 ;
      RECT 0.140 2135.840 16.100 2136.120 ;
      RECT 0.140 2138.080 16.100 2138.360 ;
      RECT 0.140 2140.320 16.100 2140.600 ;
      RECT 0.140 2142.560 16.100 2142.840 ;
      RECT 0.140 2144.800 16.100 2145.080 ;
      RECT 0.140 2147.040 16.100 2147.320 ;
      RECT 0.140 2149.280 16.100 2149.560 ;
      RECT 0.140 2151.520 16.100 2151.800 ;
      RECT 0.140 2153.760 16.100 2154.040 ;
      RECT 0.140 2156.000 16.100 2156.280 ;
      RECT 0.140 2158.240 16.100 2158.520 ;
      RECT 0.140 2160.480 16.100 2160.760 ;
      RECT 0.140 2162.720 16.100 2163.000 ;
      RECT 0.140 2164.960 16.100 2165.240 ;
      RECT 0.140 2167.200 16.100 2167.480 ;
      RECT 0.140 2169.440 16.100 2169.720 ;
      RECT 0.140 2171.680 16.100 2171.960 ;
      RECT 0.140 2173.920 16.100 2174.200 ;
      RECT 0.140 2176.160 16.100 2176.440 ;
      RECT 0.140 2178.400 16.100 2178.680 ;
      RECT 0.140 2180.640 16.100 2180.920 ;
      RECT 0.140 2182.880 16.100 2183.160 ;
      RECT 0.140 2185.120 16.100 2185.400 ;
      RECT 0.140 2187.360 16.100 2187.640 ;
      RECT 0.140 2189.600 16.100 2189.880 ;
      RECT 0.140 2191.840 16.100 2192.120 ;
      RECT 0.140 2194.080 16.100 2194.360 ;
      RECT 0.140 2196.320 16.100 2196.600 ;
      RECT 0.140 2198.560 16.100 2198.840 ;
      RECT 0.140 2200.800 16.100 2201.080 ;
      RECT 0.140 2203.040 16.100 2203.320 ;
      RECT 0.140 2205.280 16.100 2205.560 ;
      RECT 0.140 2207.520 16.100 2207.800 ;
      RECT 0.140 2209.760 16.100 2210.040 ;
      RECT 0.140 2212.000 16.100 2212.280 ;
      RECT 0.140 2214.240 16.100 2214.520 ;
      RECT 0.140 2216.480 16.100 2216.760 ;
      RECT 0.140 2218.720 16.100 2219.000 ;
      RECT 0.140 2220.960 16.100 2221.240 ;
      RECT 0.140 2223.200 16.100 2223.480 ;
      RECT 0.140 2225.440 16.100 2225.720 ;
      RECT 0.140 2227.680 16.100 2227.960 ;
      RECT 0.140 2229.920 16.100 2230.200 ;
      RECT 0.140 2232.160 16.100 2232.440 ;
      RECT 0.140 2234.400 16.100 2234.680 ;
      RECT 0.140 2236.640 16.100 2236.920 ;
      RECT 0.140 2238.880 16.100 2239.160 ;
      RECT 0.140 2241.120 16.100 2241.400 ;
      RECT 0.140 2243.360 16.100 2243.640 ;
      RECT 0.140 2245.600 16.100 2245.880 ;
      RECT 0.140 2247.840 16.100 2248.120 ;
      RECT 0.140 2250.080 16.100 2250.360 ;
      RECT 0.140 2252.320 16.100 2252.600 ;
      RECT 0.140 2254.560 16.100 2254.840 ;
      RECT 0.140 2256.800 16.100 2257.080 ;
      RECT 0.140 2259.040 16.100 2259.320 ;
      RECT 0.140 2261.280 16.100 2261.560 ;
      RECT 0.140 2263.520 16.100 2263.800 ;
      RECT 0.140 2265.760 16.100 2266.040 ;
      RECT 0.140 2268.000 16.100 2268.280 ;
      RECT 0.140 2270.240 16.100 2270.520 ;
      RECT 0.140 2272.480 16.100 2272.760 ;
      RECT 0.140 2274.720 16.100 2275.000 ;
      RECT 0.140 2276.960 16.100 2277.240 ;
      RECT 0.140 2279.200 16.100 2279.480 ;
      RECT 0.140 2281.440 16.100 2281.720 ;
      RECT 0.140 2283.680 16.100 2283.960 ;
      RECT 0.140 2285.920 16.100 2286.200 ;
      RECT 0.140 2288.160 16.100 2288.440 ;
      RECT 0.140 2290.400 16.100 2290.680 ;
      RECT 0.140 2292.640 16.100 2292.920 ;
      RECT 0.140 2294.880 16.100 2295.160 ;
      RECT 0.140 2297.120 16.100 2297.400 ;
      RECT 0.140 2299.360 16.100 2299.640 ;
      RECT 0.140 2301.600 16.100 2301.880 ;
      RECT 0.140 2303.840 16.100 2304.120 ;
      RECT 0.140 2306.080 16.100 2306.360 ;
      RECT 0.140 2308.320 16.100 2308.600 ;
      RECT 0.140 2310.560 16.100 2310.840 ;
      RECT 0.140 2312.800 16.100 2313.080 ;
      RECT 0.140 2315.040 16.100 2315.320 ;
      RECT 0.140 2317.280 16.100 2317.560 ;
      RECT 0.140 2319.520 16.100 2319.800 ;
      RECT 0.140 2321.760 16.100 2322.040 ;
      RECT 0.140 2324.000 16.100 2324.280 ;
      RECT 0.140 2326.240 16.100 2326.520 ;
      RECT 0.140 2328.480 16.100 2328.760 ;
      RECT 0.140 2330.720 16.100 2331.000 ;
      RECT 0.140 2332.960 16.100 2333.240 ;
      RECT 0.140 2335.200 16.100 2335.480 ;
      RECT 0.140 2337.440 16.100 2337.720 ;
      RECT 0.140 2339.680 16.100 2339.960 ;
      RECT 0.140 2341.920 16.100 2342.200 ;
      RECT 0.140 2344.160 16.100 2344.440 ;
      RECT 0.140 2346.400 16.100 2346.680 ;
      RECT 0.140 2348.640 16.100 2348.920 ;
      RECT 0.140 2350.880 16.100 2351.160 ;
      RECT 0.140 2353.120 16.100 2353.400 ;
      RECT 0.140 2355.360 16.100 2355.640 ;
      RECT 0.140 2357.600 16.100 2357.880 ;
      RECT 0.140 2359.840 16.100 2360.120 ;
      RECT 0.140 2362.080 16.100 2362.360 ;
      RECT 0.140 2364.320 16.100 2364.600 ;
      RECT 0.140 2366.560 16.100 2366.840 ;
      RECT 0.140 2368.800 16.100 2369.080 ;
      RECT 0.140 2371.040 16.100 2371.320 ;
      RECT 0.140 2373.280 16.100 2373.560 ;
      RECT 0.140 2375.520 16.100 2375.800 ;
      RECT 0.140 2377.760 16.100 2378.040 ;
      RECT 0.140 2380.000 16.100 2380.280 ;
      RECT 0.140 2382.240 16.100 2382.520 ;
      RECT 0.140 2384.480 16.100 2384.760 ;
      RECT 0.140 2386.720 16.100 2387.000 ;
      RECT 0.140 2388.960 16.100 2389.240 ;
      RECT 0.140 2391.200 16.100 2391.480 ;
      RECT 0.140 2393.440 16.100 2393.720 ;
      RECT 0.140 2395.680 16.100 2395.960 ;
      RECT 0.140 2397.920 16.100 2398.200 ;
      RECT 0.140 2400.160 16.100 2400.440 ;
      RECT 0.140 2402.400 16.100 2402.680 ;
      RECT 0.140 2404.640 16.100 2404.920 ;
      RECT 0.140 2406.880 16.100 2407.160 ;
      RECT 0.140 2409.120 16.100 2409.400 ;
      RECT 0.140 2411.360 16.100 2411.640 ;
      RECT 0.140 2413.600 16.100 2413.880 ;
      RECT 0.140 2415.840 16.100 2416.120 ;
      RECT 0.140 2418.080 16.100 2418.360 ;
      RECT 0.140 2420.320 16.100 2420.600 ;
      RECT 0.140 2422.560 16.100 2422.840 ;
      RECT 0.140 2424.800 16.100 2425.080 ;
      RECT 0.140 2427.040 16.100 2427.320 ;
      RECT 0.140 2429.280 16.100 2429.560 ;
      RECT 0.140 2431.520 16.100 2431.800 ;
      RECT 0.140 2433.760 16.100 2434.040 ;
      RECT 0.140 2436.000 16.100 2436.280 ;
      RECT 0.140 2438.240 16.100 2438.520 ;
      RECT 0.140 2440.480 16.100 2440.760 ;
      RECT 0.140 2442.720 16.100 2443.000 ;
      RECT 0.140 2444.960 16.100 2445.240 ;
      RECT 0.140 2447.200 16.100 2447.480 ;
      RECT 0.140 2449.440 16.100 2449.720 ;
      RECT 0.140 2451.680 16.100 2451.960 ;
      RECT 0.140 2453.920 16.100 2454.200 ;
      RECT 0.140 2456.160 16.100 2456.440 ;
      RECT 0.140 2458.400 16.100 2458.680 ;
      RECT 0.140 2460.640 16.100 2460.920 ;
      RECT 0.140 2462.880 16.100 2463.160 ;
      RECT 0.140 2465.120 16.100 2465.400 ;
      RECT 0.140 2467.360 16.100 2467.640 ;
      RECT 0.140 2469.600 16.100 2469.880 ;
      RECT 0.140 2471.840 16.100 2472.120 ;
      RECT 0.140 2474.080 16.100 2474.360 ;
      RECT 0.140 2476.320 16.100 2476.600 ;
      RECT 0.140 2478.560 16.100 2478.840 ;
      RECT 0.140 2480.800 16.100 2481.080 ;
      RECT 0.140 2483.040 16.100 2483.320 ;
      RECT 0.140 2485.280 16.100 2485.560 ;
      RECT 0.140 2487.520 16.100 2487.800 ;
      RECT 0.140 2489.760 16.100 2490.040 ;
      RECT 0.140 2492.000 16.100 2492.280 ;
      RECT 0.140 2494.240 16.100 2494.520 ;
      RECT 0.140 2496.480 16.100 2496.760 ;
      RECT 0.140 2498.720 16.100 2499.000 ;
      RECT 0.140 2500.960 16.100 2501.240 ;
      RECT 0.140 2503.200 16.100 2503.480 ;
      RECT 0.140 2505.440 16.100 2505.720 ;
      RECT 0.140 2507.680 16.100 2507.960 ;
      RECT 0.140 2509.920 16.100 2510.200 ;
      RECT 0.140 2512.160 16.100 2512.440 ;
      RECT 0.140 2514.400 16.100 2514.680 ;
      RECT 0.140 2516.640 16.100 2516.920 ;
      RECT 0.140 2518.880 16.100 2519.160 ;
      RECT 0.140 2521.120 16.100 2521.400 ;
      RECT 0.140 2523.360 16.100 2523.640 ;
      RECT 0.140 2525.600 16.100 2525.880 ;
      RECT 0.140 2527.840 16.100 2528.120 ;
      RECT 0.140 2530.080 16.100 2530.360 ;
      RECT 0.140 2532.320 16.100 2532.600 ;
      RECT 0.140 2534.560 16.100 2534.840 ;
      RECT 0.140 2536.800 16.100 2537.080 ;
      RECT 0.140 2539.040 16.100 2539.320 ;
      RECT 0.140 2541.280 16.100 2541.560 ;
      RECT 0.140 2543.520 16.100 2543.800 ;
      RECT 0.140 2545.760 16.100 2546.040 ;
      RECT 0.140 2548.000 16.100 2548.280 ;
      RECT 0.140 2550.240 16.100 2550.520 ;
      RECT 0.140 2552.480 16.100 2552.760 ;
      RECT 0.140 2554.720 16.100 2555.000 ;
      RECT 0.140 2556.960 16.100 2557.240 ;
      RECT 0.140 2559.200 16.100 2559.480 ;
      RECT 0.140 2561.440 16.100 2561.720 ;
      RECT 0.140 2563.680 16.100 2563.960 ;
      RECT 0.140 2565.920 16.100 2566.200 ;
      RECT 0.140 2568.160 16.100 2568.440 ;
      RECT 0.140 2570.400 16.100 2570.680 ;
      RECT 0.140 2572.640 16.100 2572.920 ;
      RECT 0.140 2574.880 16.100 2575.160 ;
      RECT 0.140 2577.120 16.100 2577.400 ;
      RECT 0.140 2579.360 16.100 2579.640 ;
    END
  END VDD
  OBS
    LAYER metal1 ;
    RECT 0 0 16.240 2581.600 ;
    LAYER metal2 ;
    RECT 0 0 16.240 2581.600 ;
  END
END fakeram_32x1024
END LIBRARY
